VERSION 5.8 ;
BUSBITCHARS "[]" ;
DIVIDERCHAR "/" ;
UNITS
    DATABASE MICRONS 1000 ;
END UNITS

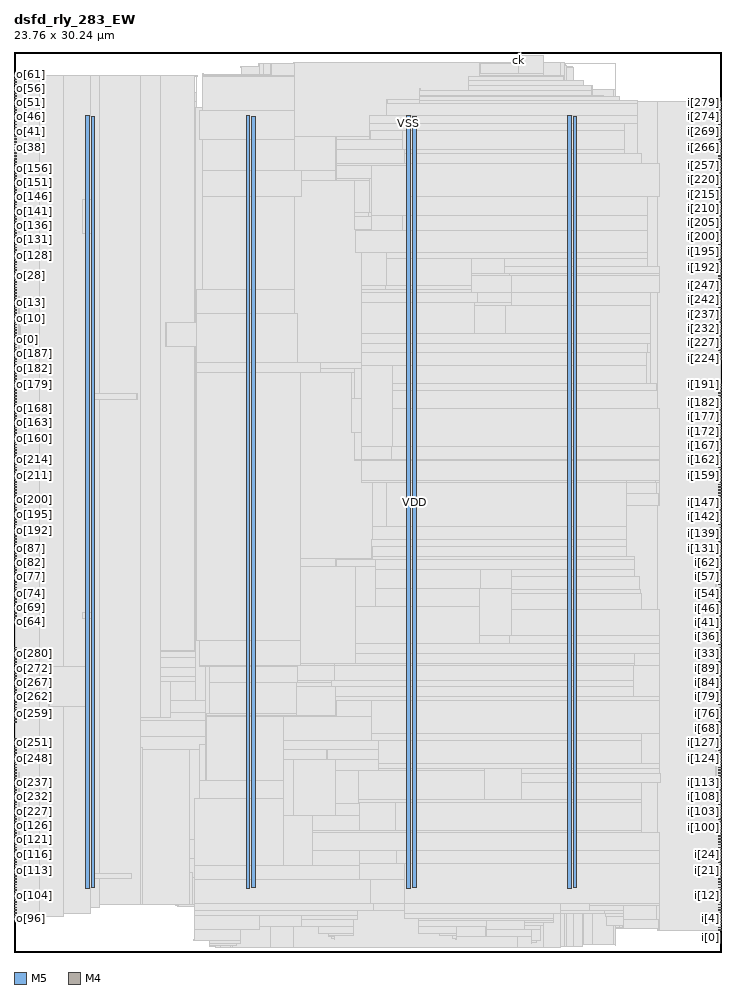
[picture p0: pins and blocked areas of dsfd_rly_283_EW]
MACRO dsfd_rly_283_EW
  FOREIGN dsfd_rly_283_EW 0 0 ;
  CLASS BLOCK ;
  SIZE 23.76 BY 30.24 ;
  PIN ck
    DIRECTION INPUT ;
    USE SIGNAL ;
    PORT
      LAYER M5 ;
        RECT  16.944 30.156 16.968 30.24 ;
    END
  END ck
  PIN i[0]
    DIRECTION INPUT ;
    USE SIGNAL ;
    PORT
      LAYER M4 ;
        RECT  23.676 0.72 23.76 0.744 ;
    END
  END i[0]
  PIN i[100]
    DIRECTION INPUT ;
    USE SIGNAL ;
    PORT
      LAYER M4 ;
        RECT  23.676 4.176 23.76 4.2 ;
    END
  END i[100]
  PIN i[101]
    DIRECTION INPUT ;
    USE SIGNAL ;
    PORT
      LAYER M4 ;
        RECT  23.676 4.272 23.76 4.296 ;
    END
  END i[101]
  PIN i[102]
    DIRECTION INPUT ;
    USE SIGNAL ;
    PORT
      LAYER M4 ;
        RECT  23.676 4.368 23.76 4.392 ;
    END
  END i[102]
  PIN i[103]
    DIRECTION INPUT ;
    USE SIGNAL ;
    PORT
      LAYER M4 ;
        RECT  23.676 4.464 23.76 4.488 ;
    END
  END i[103]
  PIN i[104]
    DIRECTION INPUT ;
    USE SIGNAL ;
    PORT
      LAYER M4 ;
        RECT  23.676 4.56 23.76 4.584 ;
    END
  END i[104]
  PIN i[105]
    DIRECTION INPUT ;
    USE SIGNAL ;
    PORT
      LAYER M4 ;
        RECT  23.676 4.656 23.76 4.68 ;
    END
  END i[105]
  PIN i[106]
    DIRECTION INPUT ;
    USE SIGNAL ;
    PORT
      LAYER M4 ;
        RECT  23.676 4.752 23.76 4.776 ;
    END
  END i[106]
  PIN i[107]
    DIRECTION INPUT ;
    USE SIGNAL ;
    PORT
      LAYER M4 ;
        RECT  23.676 4.848 23.76 4.872 ;
    END
  END i[107]
  PIN i[108]
    DIRECTION INPUT ;
    USE SIGNAL ;
    PORT
      LAYER M4 ;
        RECT  23.676 4.944 23.76 4.968 ;
    END
  END i[108]
  PIN i[109]
    DIRECTION INPUT ;
    USE SIGNAL ;
    PORT
      LAYER M4 ;
        RECT  23.676 5.04 23.76 5.064 ;
    END
  END i[109]
  PIN i[10]
    DIRECTION INPUT ;
    USE SIGNAL ;
    PORT
      LAYER M4 ;
        RECT  23.676 1.68 23.76 1.704 ;
    END
  END i[10]
  PIN i[110]
    DIRECTION INPUT ;
    USE SIGNAL ;
    PORT
      LAYER M4 ;
        RECT  23.676 5.136 23.76 5.16 ;
    END
  END i[110]
  PIN i[111]
    DIRECTION INPUT ;
    USE SIGNAL ;
    PORT
      LAYER M4 ;
        RECT  23.676 5.232 23.76 5.256 ;
    END
  END i[111]
  PIN i[112]
    DIRECTION INPUT ;
    USE SIGNAL ;
    PORT
      LAYER M4 ;
        RECT  23.676 5.328 23.76 5.352 ;
    END
  END i[112]
  PIN i[113]
    DIRECTION INPUT ;
    USE SIGNAL ;
    PORT
      LAYER M4 ;
        RECT  23.676 5.424 23.76 5.448 ;
    END
  END i[113]
  PIN i[114]
    DIRECTION INPUT ;
    USE SIGNAL ;
    PORT
      LAYER M4 ;
        RECT  23.676 5.52 23.76 5.544 ;
    END
  END i[114]
  PIN i[115]
    DIRECTION INPUT ;
    USE SIGNAL ;
    PORT
      LAYER M4 ;
        RECT  23.676 5.616 23.76 5.64 ;
    END
  END i[115]
  PIN i[116]
    DIRECTION INPUT ;
    USE SIGNAL ;
    PORT
      LAYER M4 ;
        RECT  23.676 5.712 23.76 5.736 ;
    END
  END i[116]
  PIN i[117]
    DIRECTION INPUT ;
    USE SIGNAL ;
    PORT
      LAYER M4 ;
        RECT  23.676 5.808 23.76 5.832 ;
    END
  END i[117]
  PIN i[118]
    DIRECTION INPUT ;
    USE SIGNAL ;
    PORT
      LAYER M4 ;
        RECT  23.676 5.904 23.76 5.928 ;
    END
  END i[118]
  PIN i[119]
    DIRECTION INPUT ;
    USE SIGNAL ;
    PORT
      LAYER M4 ;
        RECT  23.676 6 23.76 6.024 ;
    END
  END i[119]
  PIN i[11]
    DIRECTION INPUT ;
    USE SIGNAL ;
    PORT
      LAYER M4 ;
        RECT  23.676 1.776 23.76 1.8 ;
    END
  END i[11]
  PIN i[120]
    DIRECTION INPUT ;
    USE SIGNAL ;
    PORT
      LAYER M4 ;
        RECT  23.676 6.096 23.76 6.12 ;
    END
  END i[120]
  PIN i[121]
    DIRECTION INPUT ;
    USE SIGNAL ;
    PORT
      LAYER M4 ;
        RECT  23.676 6.192 23.76 6.216 ;
    END
  END i[121]
  PIN i[122]
    DIRECTION INPUT ;
    USE SIGNAL ;
    PORT
      LAYER M4 ;
        RECT  23.676 6.288 23.76 6.312 ;
    END
  END i[122]
  PIN i[123]
    DIRECTION INPUT ;
    USE SIGNAL ;
    PORT
      LAYER M4 ;
        RECT  23.676 6.384 23.76 6.408 ;
    END
  END i[123]
  PIN i[124]
    DIRECTION INPUT ;
    USE SIGNAL ;
    PORT
      LAYER M4 ;
        RECT  23.676 6.48 23.76 6.504 ;
    END
  END i[124]
  PIN i[125]
    DIRECTION INPUT ;
    USE SIGNAL ;
    PORT
      LAYER M4 ;
        RECT  23.676 6.576 23.76 6.6 ;
    END
  END i[125]
  PIN i[126]
    DIRECTION INPUT ;
    USE SIGNAL ;
    PORT
      LAYER M4 ;
        RECT  23.676 6.672 23.76 6.696 ;
    END
  END i[126]
  PIN i[127]
    DIRECTION INPUT ;
    USE SIGNAL ;
    PORT
      LAYER M4 ;
        RECT  23.676 6.768 23.76 6.792 ;
    END
  END i[127]
  PIN i[128]
    DIRECTION INPUT ;
    USE SIGNAL ;
    PORT
      LAYER M4 ;
        RECT  23.676 13.008 23.76 13.032 ;
    END
  END i[128]
  PIN i[129]
    DIRECTION INPUT ;
    USE SIGNAL ;
    PORT
      LAYER M4 ;
        RECT  23.676 13.104 23.76 13.128 ;
    END
  END i[129]
  PIN i[12]
    DIRECTION INPUT ;
    USE SIGNAL ;
    PORT
      LAYER M4 ;
        RECT  23.676 1.872 23.76 1.896 ;
    END
  END i[12]
  PIN i[130]
    DIRECTION INPUT ;
    USE SIGNAL ;
    PORT
      LAYER M4 ;
        RECT  23.676 13.2 23.76 13.224 ;
    END
  END i[130]
  PIN i[131]
    DIRECTION INPUT ;
    USE SIGNAL ;
    PORT
      LAYER M4 ;
        RECT  23.676 13.296 23.76 13.32 ;
    END
  END i[131]
  PIN i[132]
    DIRECTION INPUT ;
    USE SIGNAL ;
    PORT
      LAYER M4 ;
        RECT  23.676 13.392 23.76 13.416 ;
    END
  END i[132]
  PIN i[133]
    DIRECTION INPUT ;
    USE SIGNAL ;
    PORT
      LAYER M4 ;
        RECT  23.676 13.488 23.76 13.512 ;
    END
  END i[133]
  PIN i[134]
    DIRECTION INPUT ;
    USE SIGNAL ;
    PORT
      LAYER M4 ;
        RECT  23.676 13.584 23.76 13.608 ;
    END
  END i[134]
  PIN i[135]
    DIRECTION INPUT ;
    USE SIGNAL ;
    PORT
      LAYER M4 ;
        RECT  23.676 13.68 23.76 13.704 ;
    END
  END i[135]
  PIN i[136]
    DIRECTION INPUT ;
    USE SIGNAL ;
    PORT
      LAYER M4 ;
        RECT  23.676 13.776 23.76 13.8 ;
    END
  END i[136]
  PIN i[137]
    DIRECTION INPUT ;
    USE SIGNAL ;
    PORT
      LAYER M4 ;
        RECT  23.676 13.872 23.76 13.896 ;
    END
  END i[137]
  PIN i[138]
    DIRECTION INPUT ;
    USE SIGNAL ;
    PORT
      LAYER M4 ;
        RECT  23.676 13.968 23.76 13.992 ;
    END
  END i[138]
  PIN i[139]
    DIRECTION INPUT ;
    USE SIGNAL ;
    PORT
      LAYER M4 ;
        RECT  23.676 14.064 23.76 14.088 ;
    END
  END i[139]
  PIN i[13]
    DIRECTION INPUT ;
    USE SIGNAL ;
    PORT
      LAYER M4 ;
        RECT  23.676 1.968 23.76 1.992 ;
    END
  END i[13]
  PIN i[140]
    DIRECTION INPUT ;
    USE SIGNAL ;
    PORT
      LAYER M4 ;
        RECT  23.676 14.16 23.76 14.184 ;
    END
  END i[140]
  PIN i[141]
    DIRECTION INPUT ;
    USE SIGNAL ;
    PORT
      LAYER M4 ;
        RECT  23.676 14.256 23.76 14.28 ;
    END
  END i[141]
  PIN i[142]
    DIRECTION INPUT ;
    USE SIGNAL ;
    PORT
      LAYER M4 ;
        RECT  23.676 14.352 23.76 14.376 ;
    END
  END i[142]
  PIN i[143]
    DIRECTION INPUT ;
    USE SIGNAL ;
    PORT
      LAYER M4 ;
        RECT  23.676 14.448 23.76 14.472 ;
    END
  END i[143]
  PIN i[144]
    DIRECTION INPUT ;
    USE SIGNAL ;
    PORT
      LAYER M4 ;
        RECT  23.676 14.544 23.76 14.568 ;
    END
  END i[144]
  PIN i[145]
    DIRECTION INPUT ;
    USE SIGNAL ;
    PORT
      LAYER M4 ;
        RECT  23.676 14.64 23.76 14.664 ;
    END
  END i[145]
  PIN i[146]
    DIRECTION INPUT ;
    USE SIGNAL ;
    PORT
      LAYER M4 ;
        RECT  23.676 14.736 23.76 14.76 ;
    END
  END i[146]
  PIN i[147]
    DIRECTION INPUT ;
    USE SIGNAL ;
    PORT
      LAYER M4 ;
        RECT  23.676 14.832 23.76 14.856 ;
    END
  END i[147]
  PIN i[148]
    DIRECTION INPUT ;
    USE SIGNAL ;
    PORT
      LAYER M4 ;
        RECT  23.676 14.928 23.76 14.952 ;
    END
  END i[148]
  PIN i[149]
    DIRECTION INPUT ;
    USE SIGNAL ;
    PORT
      LAYER M4 ;
        RECT  23.676 15.024 23.76 15.048 ;
    END
  END i[149]
  PIN i[14]
    DIRECTION INPUT ;
    USE SIGNAL ;
    PORT
      LAYER M4 ;
        RECT  23.676 2.064 23.76 2.088 ;
    END
  END i[14]
  PIN i[150]
    DIRECTION INPUT ;
    USE SIGNAL ;
    PORT
      LAYER M4 ;
        RECT  23.676 15.12 23.76 15.144 ;
    END
  END i[150]
  PIN i[151]
    DIRECTION INPUT ;
    USE SIGNAL ;
    PORT
      LAYER M4 ;
        RECT  23.676 15.216 23.76 15.24 ;
    END
  END i[151]
  PIN i[152]
    DIRECTION INPUT ;
    USE SIGNAL ;
    PORT
      LAYER M4 ;
        RECT  23.676 15.312 23.76 15.336 ;
    END
  END i[152]
  PIN i[153]
    DIRECTION INPUT ;
    USE SIGNAL ;
    PORT
      LAYER M4 ;
        RECT  23.676 15.408 23.76 15.432 ;
    END
  END i[153]
  PIN i[154]
    DIRECTION INPUT ;
    USE SIGNAL ;
    PORT
      LAYER M4 ;
        RECT  23.676 15.504 23.76 15.528 ;
    END
  END i[154]
  PIN i[155]
    DIRECTION INPUT ;
    USE SIGNAL ;
    PORT
      LAYER M4 ;
        RECT  23.676 15.6 23.76 15.624 ;
    END
  END i[155]
  PIN i[156]
    DIRECTION INPUT ;
    USE SIGNAL ;
    PORT
      LAYER M4 ;
        RECT  23.676 15.696 23.76 15.72 ;
    END
  END i[156]
  PIN i[157]
    DIRECTION INPUT ;
    USE SIGNAL ;
    PORT
      LAYER M4 ;
        RECT  23.676 15.792 23.76 15.816 ;
    END
  END i[157]
  PIN i[158]
    DIRECTION INPUT ;
    USE SIGNAL ;
    PORT
      LAYER M4 ;
        RECT  23.676 15.888 23.76 15.912 ;
    END
  END i[158]
  PIN i[159]
    DIRECTION INPUT ;
    USE SIGNAL ;
    PORT
      LAYER M4 ;
        RECT  23.676 15.984 23.76 16.008 ;
    END
  END i[159]
  PIN i[15]
    DIRECTION INPUT ;
    USE SIGNAL ;
    PORT
      LAYER M4 ;
        RECT  23.676 2.16 23.76 2.184 ;
    END
  END i[15]
  PIN i[160]
    DIRECTION INPUT ;
    USE SIGNAL ;
    PORT
      LAYER M4 ;
        RECT  23.676 16.08 23.76 16.104 ;
    END
  END i[160]
  PIN i[161]
    DIRECTION INPUT ;
    USE SIGNAL ;
    PORT
      LAYER M4 ;
        RECT  23.676 16.176 23.76 16.2 ;
    END
  END i[161]
  PIN i[162]
    DIRECTION INPUT ;
    USE SIGNAL ;
    PORT
      LAYER M4 ;
        RECT  23.676 16.272 23.76 16.296 ;
    END
  END i[162]
  PIN i[163]
    DIRECTION INPUT ;
    USE SIGNAL ;
    PORT
      LAYER M4 ;
        RECT  23.676 16.368 23.76 16.392 ;
    END
  END i[163]
  PIN i[164]
    DIRECTION INPUT ;
    USE SIGNAL ;
    PORT
      LAYER M4 ;
        RECT  23.676 16.464 23.76 16.488 ;
    END
  END i[164]
  PIN i[165]
    DIRECTION INPUT ;
    USE SIGNAL ;
    PORT
      LAYER M4 ;
        RECT  23.676 16.56 23.76 16.584 ;
    END
  END i[165]
  PIN i[166]
    DIRECTION INPUT ;
    USE SIGNAL ;
    PORT
      LAYER M4 ;
        RECT  23.676 16.656 23.76 16.68 ;
    END
  END i[166]
  PIN i[167]
    DIRECTION INPUT ;
    USE SIGNAL ;
    PORT
      LAYER M4 ;
        RECT  23.676 16.752 23.76 16.776 ;
    END
  END i[167]
  PIN i[168]
    DIRECTION INPUT ;
    USE SIGNAL ;
    PORT
      LAYER M4 ;
        RECT  23.676 16.848 23.76 16.872 ;
    END
  END i[168]
  PIN i[169]
    DIRECTION INPUT ;
    USE SIGNAL ;
    PORT
      LAYER M4 ;
        RECT  23.676 16.944 23.76 16.968 ;
    END
  END i[169]
  PIN i[16]
    DIRECTION INPUT ;
    USE SIGNAL ;
    PORT
      LAYER M4 ;
        RECT  23.676 2.256 23.76 2.28 ;
    END
  END i[16]
  PIN i[170]
    DIRECTION INPUT ;
    USE SIGNAL ;
    PORT
      LAYER M4 ;
        RECT  23.676 17.04 23.76 17.064 ;
    END
  END i[170]
  PIN i[171]
    DIRECTION INPUT ;
    USE SIGNAL ;
    PORT
      LAYER M4 ;
        RECT  23.676 17.136 23.76 17.16 ;
    END
  END i[171]
  PIN i[172]
    DIRECTION INPUT ;
    USE SIGNAL ;
    PORT
      LAYER M4 ;
        RECT  23.676 17.232 23.76 17.256 ;
    END
  END i[172]
  PIN i[173]
    DIRECTION INPUT ;
    USE SIGNAL ;
    PORT
      LAYER M4 ;
        RECT  23.676 17.328 23.76 17.352 ;
    END
  END i[173]
  PIN i[174]
    DIRECTION INPUT ;
    USE SIGNAL ;
    PORT
      LAYER M4 ;
        RECT  23.676 17.424 23.76 17.448 ;
    END
  END i[174]
  PIN i[175]
    DIRECTION INPUT ;
    USE SIGNAL ;
    PORT
      LAYER M4 ;
        RECT  23.676 17.52 23.76 17.544 ;
    END
  END i[175]
  PIN i[176]
    DIRECTION INPUT ;
    USE SIGNAL ;
    PORT
      LAYER M4 ;
        RECT  23.676 17.616 23.76 17.64 ;
    END
  END i[176]
  PIN i[177]
    DIRECTION INPUT ;
    USE SIGNAL ;
    PORT
      LAYER M4 ;
        RECT  23.676 17.712 23.76 17.736 ;
    END
  END i[177]
  PIN i[178]
    DIRECTION INPUT ;
    USE SIGNAL ;
    PORT
      LAYER M4 ;
        RECT  23.676 17.808 23.76 17.832 ;
    END
  END i[178]
  PIN i[179]
    DIRECTION INPUT ;
    USE SIGNAL ;
    PORT
      LAYER M4 ;
        RECT  23.676 17.904 23.76 17.928 ;
    END
  END i[179]
  PIN i[17]
    DIRECTION INPUT ;
    USE SIGNAL ;
    PORT
      LAYER M4 ;
        RECT  23.676 2.352 23.76 2.376 ;
    END
  END i[17]
  PIN i[180]
    DIRECTION INPUT ;
    USE SIGNAL ;
    PORT
      LAYER M4 ;
        RECT  23.676 18 23.76 18.024 ;
    END
  END i[180]
  PIN i[181]
    DIRECTION INPUT ;
    USE SIGNAL ;
    PORT
      LAYER M4 ;
        RECT  23.676 18.096 23.76 18.12 ;
    END
  END i[181]
  PIN i[182]
    DIRECTION INPUT ;
    USE SIGNAL ;
    PORT
      LAYER M4 ;
        RECT  23.676 18.192 23.76 18.216 ;
    END
  END i[182]
  PIN i[183]
    DIRECTION INPUT ;
    USE SIGNAL ;
    PORT
      LAYER M4 ;
        RECT  23.676 18.288 23.76 18.312 ;
    END
  END i[183]
  PIN i[184]
    DIRECTION INPUT ;
    USE SIGNAL ;
    PORT
      LAYER M4 ;
        RECT  23.676 18.384 23.76 18.408 ;
    END
  END i[184]
  PIN i[185]
    DIRECTION INPUT ;
    USE SIGNAL ;
    PORT
      LAYER M4 ;
        RECT  23.676 18.48 23.76 18.504 ;
    END
  END i[185]
  PIN i[186]
    DIRECTION INPUT ;
    USE SIGNAL ;
    PORT
      LAYER M4 ;
        RECT  23.676 18.576 23.76 18.6 ;
    END
  END i[186]
  PIN i[187]
    DIRECTION INPUT ;
    USE SIGNAL ;
    PORT
      LAYER M4 ;
        RECT  23.676 18.672 23.76 18.696 ;
    END
  END i[187]
  PIN i[188]
    DIRECTION INPUT ;
    USE SIGNAL ;
    PORT
      LAYER M4 ;
        RECT  23.676 18.768 23.76 18.792 ;
    END
  END i[188]
  PIN i[189]
    DIRECTION INPUT ;
    USE SIGNAL ;
    PORT
      LAYER M4 ;
        RECT  23.676 18.864 23.76 18.888 ;
    END
  END i[189]
  PIN i[18]
    DIRECTION INPUT ;
    USE SIGNAL ;
    PORT
      LAYER M4 ;
        RECT  23.676 2.448 23.76 2.472 ;
    END
  END i[18]
  PIN i[190]
    DIRECTION INPUT ;
    USE SIGNAL ;
    PORT
      LAYER M4 ;
        RECT  23.676 18.96 23.76 18.984 ;
    END
  END i[190]
  PIN i[191]
    DIRECTION INPUT ;
    USE SIGNAL ;
    PORT
      LAYER M4 ;
        RECT  23.676 19.056 23.76 19.08 ;
    END
  END i[191]
  PIN i[192]
    DIRECTION INPUT ;
    USE SIGNAL ;
    PORT
      LAYER M4 ;
        RECT  23.676 22.992 23.76 23.016 ;
    END
  END i[192]
  PIN i[193]
    DIRECTION INPUT ;
    USE SIGNAL ;
    PORT
      LAYER M4 ;
        RECT  23.676 23.088 23.76 23.112 ;
    END
  END i[193]
  PIN i[194]
    DIRECTION INPUT ;
    USE SIGNAL ;
    PORT
      LAYER M4 ;
        RECT  23.676 23.184 23.76 23.208 ;
    END
  END i[194]
  PIN i[195]
    DIRECTION INPUT ;
    USE SIGNAL ;
    PORT
      LAYER M4 ;
        RECT  23.676 23.28 23.76 23.304 ;
    END
  END i[195]
  PIN i[196]
    DIRECTION INPUT ;
    USE SIGNAL ;
    PORT
      LAYER M4 ;
        RECT  23.676 23.376 23.76 23.4 ;
    END
  END i[196]
  PIN i[197]
    DIRECTION INPUT ;
    USE SIGNAL ;
    PORT
      LAYER M4 ;
        RECT  23.676 23.472 23.76 23.496 ;
    END
  END i[197]
  PIN i[198]
    DIRECTION INPUT ;
    USE SIGNAL ;
    PORT
      LAYER M4 ;
        RECT  23.676 23.568 23.76 23.592 ;
    END
  END i[198]
  PIN i[199]
    DIRECTION INPUT ;
    USE SIGNAL ;
    PORT
      LAYER M4 ;
        RECT  23.676 23.664 23.76 23.688 ;
    END
  END i[199]
  PIN i[19]
    DIRECTION INPUT ;
    USE SIGNAL ;
    PORT
      LAYER M4 ;
        RECT  23.676 2.544 23.76 2.568 ;
    END
  END i[19]
  PIN i[1]
    DIRECTION INPUT ;
    USE SIGNAL ;
    PORT
      LAYER M4 ;
        RECT  23.676 0.816 23.76 0.84 ;
    END
  END i[1]
  PIN i[200]
    DIRECTION INPUT ;
    USE SIGNAL ;
    PORT
      LAYER M4 ;
        RECT  23.676 23.76 23.76 23.784 ;
    END
  END i[200]
  PIN i[201]
    DIRECTION INPUT ;
    USE SIGNAL ;
    PORT
      LAYER M4 ;
        RECT  23.676 23.856 23.76 23.88 ;
    END
  END i[201]
  PIN i[202]
    DIRECTION INPUT ;
    USE SIGNAL ;
    PORT
      LAYER M4 ;
        RECT  23.676 23.952 23.76 23.976 ;
    END
  END i[202]
  PIN i[203]
    DIRECTION INPUT ;
    USE SIGNAL ;
    PORT
      LAYER M4 ;
        RECT  23.676 24.048 23.76 24.072 ;
    END
  END i[203]
  PIN i[204]
    DIRECTION INPUT ;
    USE SIGNAL ;
    PORT
      LAYER M4 ;
        RECT  23.676 24.144 23.76 24.168 ;
    END
  END i[204]
  PIN i[205]
    DIRECTION INPUT ;
    USE SIGNAL ;
    PORT
      LAYER M4 ;
        RECT  23.676 24.24 23.76 24.264 ;
    END
  END i[205]
  PIN i[206]
    DIRECTION INPUT ;
    USE SIGNAL ;
    PORT
      LAYER M4 ;
        RECT  23.676 24.336 23.76 24.36 ;
    END
  END i[206]
  PIN i[207]
    DIRECTION INPUT ;
    USE SIGNAL ;
    PORT
      LAYER M4 ;
        RECT  23.676 24.432 23.76 24.456 ;
    END
  END i[207]
  PIN i[208]
    DIRECTION INPUT ;
    USE SIGNAL ;
    PORT
      LAYER M4 ;
        RECT  23.676 24.528 23.76 24.552 ;
    END
  END i[208]
  PIN i[209]
    DIRECTION INPUT ;
    USE SIGNAL ;
    PORT
      LAYER M4 ;
        RECT  23.676 24.624 23.76 24.648 ;
    END
  END i[209]
  PIN i[20]
    DIRECTION INPUT ;
    USE SIGNAL ;
    PORT
      LAYER M4 ;
        RECT  23.676 2.64 23.76 2.664 ;
    END
  END i[20]
  PIN i[210]
    DIRECTION INPUT ;
    USE SIGNAL ;
    PORT
      LAYER M4 ;
        RECT  23.676 24.72 23.76 24.744 ;
    END
  END i[210]
  PIN i[211]
    DIRECTION INPUT ;
    USE SIGNAL ;
    PORT
      LAYER M4 ;
        RECT  23.676 24.816 23.76 24.84 ;
    END
  END i[211]
  PIN i[212]
    DIRECTION INPUT ;
    USE SIGNAL ;
    PORT
      LAYER M4 ;
        RECT  23.676 24.912 23.76 24.936 ;
    END
  END i[212]
  PIN i[213]
    DIRECTION INPUT ;
    USE SIGNAL ;
    PORT
      LAYER M4 ;
        RECT  23.676 25.008 23.76 25.032 ;
    END
  END i[213]
  PIN i[214]
    DIRECTION INPUT ;
    USE SIGNAL ;
    PORT
      LAYER M4 ;
        RECT  23.676 25.104 23.76 25.128 ;
    END
  END i[214]
  PIN i[215]
    DIRECTION INPUT ;
    USE SIGNAL ;
    PORT
      LAYER M4 ;
        RECT  23.676 25.2 23.76 25.224 ;
    END
  END i[215]
  PIN i[216]
    DIRECTION INPUT ;
    USE SIGNAL ;
    PORT
      LAYER M4 ;
        RECT  23.676 25.296 23.76 25.32 ;
    END
  END i[216]
  PIN i[217]
    DIRECTION INPUT ;
    USE SIGNAL ;
    PORT
      LAYER M4 ;
        RECT  23.676 25.392 23.76 25.416 ;
    END
  END i[217]
  PIN i[218]
    DIRECTION INPUT ;
    USE SIGNAL ;
    PORT
      LAYER M4 ;
        RECT  23.676 25.488 23.76 25.512 ;
    END
  END i[218]
  PIN i[219]
    DIRECTION INPUT ;
    USE SIGNAL ;
    PORT
      LAYER M4 ;
        RECT  23.676 25.584 23.76 25.608 ;
    END
  END i[219]
  PIN i[21]
    DIRECTION INPUT ;
    USE SIGNAL ;
    PORT
      LAYER M4 ;
        RECT  23.676 2.736 23.76 2.76 ;
    END
  END i[21]
  PIN i[220]
    DIRECTION INPUT ;
    USE SIGNAL ;
    PORT
      LAYER M4 ;
        RECT  23.676 25.68 23.76 25.704 ;
    END
  END i[220]
  PIN i[221]
    DIRECTION INPUT ;
    USE SIGNAL ;
    PORT
      LAYER M4 ;
        RECT  23.676 25.776 23.76 25.8 ;
    END
  END i[221]
  PIN i[222]
    DIRECTION INPUT ;
    USE SIGNAL ;
    PORT
      LAYER M4 ;
        RECT  23.676 25.872 23.76 25.896 ;
    END
  END i[222]
  PIN i[223]
    DIRECTION INPUT ;
    USE SIGNAL ;
    PORT
      LAYER M4 ;
        RECT  23.676 25.968 23.76 25.992 ;
    END
  END i[223]
  PIN i[224]
    DIRECTION INPUT ;
    USE SIGNAL ;
    PORT
      LAYER M4 ;
        RECT  23.676 19.92 23.76 19.944 ;
    END
  END i[224]
  PIN i[225]
    DIRECTION INPUT ;
    USE SIGNAL ;
    PORT
      LAYER M4 ;
        RECT  23.676 20.016 23.76 20.04 ;
    END
  END i[225]
  PIN i[226]
    DIRECTION INPUT ;
    USE SIGNAL ;
    PORT
      LAYER M4 ;
        RECT  23.676 20.112 23.76 20.136 ;
    END
  END i[226]
  PIN i[227]
    DIRECTION INPUT ;
    USE SIGNAL ;
    PORT
      LAYER M4 ;
        RECT  23.676 20.208 23.76 20.232 ;
    END
  END i[227]
  PIN i[228]
    DIRECTION INPUT ;
    USE SIGNAL ;
    PORT
      LAYER M4 ;
        RECT  23.676 20.304 23.76 20.328 ;
    END
  END i[228]
  PIN i[229]
    DIRECTION INPUT ;
    USE SIGNAL ;
    PORT
      LAYER M4 ;
        RECT  23.676 20.4 23.76 20.424 ;
    END
  END i[229]
  PIN i[22]
    DIRECTION INPUT ;
    USE SIGNAL ;
    PORT
      LAYER M4 ;
        RECT  23.676 2.832 23.76 2.856 ;
    END
  END i[22]
  PIN i[230]
    DIRECTION INPUT ;
    USE SIGNAL ;
    PORT
      LAYER M4 ;
        RECT  23.676 20.496 23.76 20.52 ;
    END
  END i[230]
  PIN i[231]
    DIRECTION INPUT ;
    USE SIGNAL ;
    PORT
      LAYER M4 ;
        RECT  23.676 20.592 23.76 20.616 ;
    END
  END i[231]
  PIN i[232]
    DIRECTION INPUT ;
    USE SIGNAL ;
    PORT
      LAYER M4 ;
        RECT  23.676 20.688 23.76 20.712 ;
    END
  END i[232]
  PIN i[233]
    DIRECTION INPUT ;
    USE SIGNAL ;
    PORT
      LAYER M4 ;
        RECT  23.676 20.784 23.76 20.808 ;
    END
  END i[233]
  PIN i[234]
    DIRECTION INPUT ;
    USE SIGNAL ;
    PORT
      LAYER M4 ;
        RECT  23.676 20.88 23.76 20.904 ;
    END
  END i[234]
  PIN i[235]
    DIRECTION INPUT ;
    USE SIGNAL ;
    PORT
      LAYER M4 ;
        RECT  23.676 20.976 23.76 21 ;
    END
  END i[235]
  PIN i[236]
    DIRECTION INPUT ;
    USE SIGNAL ;
    PORT
      LAYER M4 ;
        RECT  23.676 21.072 23.76 21.096 ;
    END
  END i[236]
  PIN i[237]
    DIRECTION INPUT ;
    USE SIGNAL ;
    PORT
      LAYER M4 ;
        RECT  23.676 21.168 23.76 21.192 ;
    END
  END i[237]
  PIN i[238]
    DIRECTION INPUT ;
    USE SIGNAL ;
    PORT
      LAYER M4 ;
        RECT  23.676 21.264 23.76 21.288 ;
    END
  END i[238]
  PIN i[239]
    DIRECTION INPUT ;
    USE SIGNAL ;
    PORT
      LAYER M4 ;
        RECT  23.676 21.36 23.76 21.384 ;
    END
  END i[239]
  PIN i[23]
    DIRECTION INPUT ;
    USE SIGNAL ;
    PORT
      LAYER M4 ;
        RECT  23.676 2.928 23.76 2.952 ;
    END
  END i[23]
  PIN i[240]
    DIRECTION INPUT ;
    USE SIGNAL ;
    PORT
      LAYER M4 ;
        RECT  23.676 21.456 23.76 21.48 ;
    END
  END i[240]
  PIN i[241]
    DIRECTION INPUT ;
    USE SIGNAL ;
    PORT
      LAYER M4 ;
        RECT  23.676 21.552 23.76 21.576 ;
    END
  END i[241]
  PIN i[242]
    DIRECTION INPUT ;
    USE SIGNAL ;
    PORT
      LAYER M4 ;
        RECT  23.676 21.648 23.76 21.672 ;
    END
  END i[242]
  PIN i[243]
    DIRECTION INPUT ;
    USE SIGNAL ;
    PORT
      LAYER M4 ;
        RECT  23.676 21.744 23.76 21.768 ;
    END
  END i[243]
  PIN i[244]
    DIRECTION INPUT ;
    USE SIGNAL ;
    PORT
      LAYER M4 ;
        RECT  23.676 21.84 23.76 21.864 ;
    END
  END i[244]
  PIN i[245]
    DIRECTION INPUT ;
    USE SIGNAL ;
    PORT
      LAYER M4 ;
        RECT  23.676 21.936 23.76 21.96 ;
    END
  END i[245]
  PIN i[246]
    DIRECTION INPUT ;
    USE SIGNAL ;
    PORT
      LAYER M4 ;
        RECT  23.676 22.032 23.76 22.056 ;
    END
  END i[246]
  PIN i[247]
    DIRECTION INPUT ;
    USE SIGNAL ;
    PORT
      LAYER M4 ;
        RECT  23.676 22.128 23.76 22.152 ;
    END
  END i[247]
  PIN i[248]
    DIRECTION INPUT ;
    USE SIGNAL ;
    PORT
      LAYER M4 ;
        RECT  23.676 22.224 23.76 22.248 ;
    END
  END i[248]
  PIN i[249]
    DIRECTION INPUT ;
    USE SIGNAL ;
    PORT
      LAYER M4 ;
        RECT  23.676 22.32 23.76 22.344 ;
    END
  END i[249]
  PIN i[24]
    DIRECTION INPUT ;
    USE SIGNAL ;
    PORT
      LAYER M4 ;
        RECT  23.676 3.024 23.76 3.048 ;
    END
  END i[24]
  PIN i[250]
    DIRECTION INPUT ;
    USE SIGNAL ;
    PORT
      LAYER M4 ;
        RECT  23.676 22.416 23.76 22.44 ;
    END
  END i[250]
  PIN i[251]
    DIRECTION INPUT ;
    USE SIGNAL ;
    PORT
      LAYER M4 ;
        RECT  23.676 22.512 23.76 22.536 ;
    END
  END i[251]
  PIN i[252]
    DIRECTION INPUT ;
    USE SIGNAL ;
    PORT
      LAYER M4 ;
        RECT  23.676 22.608 23.76 22.632 ;
    END
  END i[252]
  PIN i[253]
    DIRECTION INPUT ;
    USE SIGNAL ;
    PORT
      LAYER M4 ;
        RECT  23.676 22.704 23.76 22.728 ;
    END
  END i[253]
  PIN i[254]
    DIRECTION INPUT ;
    USE SIGNAL ;
    PORT
      LAYER M4 ;
        RECT  23.676 22.8 23.76 22.824 ;
    END
  END i[254]
  PIN i[255]
    DIRECTION INPUT ;
    USE SIGNAL ;
    PORT
      LAYER M4 ;
        RECT  23.676 22.896 23.76 22.92 ;
    END
  END i[255]
  PIN i[256]
    DIRECTION INPUT ;
    USE SIGNAL ;
    PORT
      LAYER M4 ;
        RECT  23.676 26.064 23.76 26.088 ;
    END
  END i[256]
  PIN i[257]
    DIRECTION INPUT ;
    USE SIGNAL ;
    PORT
      LAYER M4 ;
        RECT  23.676 26.16 23.76 26.184 ;
    END
  END i[257]
  PIN i[258]
    DIRECTION INPUT ;
    USE SIGNAL ;
    PORT
      LAYER M4 ;
        RECT  23.676 26.256 23.76 26.28 ;
    END
  END i[258]
  PIN i[259]
    DIRECTION INPUT ;
    USE SIGNAL ;
    PORT
      LAYER M4 ;
        RECT  23.676 26.352 23.76 26.376 ;
    END
  END i[259]
  PIN i[25]
    DIRECTION INPUT ;
    USE SIGNAL ;
    PORT
      LAYER M4 ;
        RECT  23.676 3.12 23.76 3.144 ;
    END
  END i[25]
  PIN i[260]
    DIRECTION INPUT ;
    USE SIGNAL ;
    PORT
      LAYER M4 ;
        RECT  23.676 26.448 23.76 26.472 ;
    END
  END i[260]
  PIN i[261]
    DIRECTION INPUT ;
    USE SIGNAL ;
    PORT
      LAYER M4 ;
        RECT  23.676 26.544 23.76 26.568 ;
    END
  END i[261]
  PIN i[262]
    DIRECTION INPUT ;
    USE SIGNAL ;
    PORT
      LAYER M4 ;
        RECT  23.676 26.64 23.76 26.664 ;
    END
  END i[262]
  PIN i[263]
    DIRECTION INPUT ;
    USE SIGNAL ;
    PORT
      LAYER M4 ;
        RECT  23.676 26.736 23.76 26.76 ;
    END
  END i[263]
  PIN i[264]
    DIRECTION INPUT ;
    USE SIGNAL ;
    PORT
      LAYER M4 ;
        RECT  23.676 26.832 23.76 26.856 ;
    END
  END i[264]
  PIN i[265]
    DIRECTION INPUT ;
    USE SIGNAL ;
    PORT
      LAYER M4 ;
        RECT  23.676 26.928 23.76 26.952 ;
    END
  END i[265]
  PIN i[266]
    DIRECTION INPUT ;
    USE SIGNAL ;
    PORT
      LAYER M4 ;
        RECT  23.676 27.024 23.76 27.048 ;
    END
  END i[266]
  PIN i[267]
    DIRECTION INPUT ;
    USE SIGNAL ;
    PORT
      LAYER M4 ;
        RECT  23.676 27.12 23.76 27.144 ;
    END
  END i[267]
  PIN i[268]
    DIRECTION INPUT ;
    USE SIGNAL ;
    PORT
      LAYER M4 ;
        RECT  23.676 27.216 23.76 27.24 ;
    END
  END i[268]
  PIN i[269]
    DIRECTION INPUT ;
    USE SIGNAL ;
    PORT
      LAYER M4 ;
        RECT  23.676 27.312 23.76 27.336 ;
    END
  END i[269]
  PIN i[26]
    DIRECTION INPUT ;
    USE SIGNAL ;
    PORT
      LAYER M4 ;
        RECT  23.676 3.216 23.76 3.24 ;
    END
  END i[26]
  PIN i[270]
    DIRECTION INPUT ;
    USE SIGNAL ;
    PORT
      LAYER M4 ;
        RECT  23.676 27.408 23.76 27.432 ;
    END
  END i[270]
  PIN i[271]
    DIRECTION INPUT ;
    USE SIGNAL ;
    PORT
      LAYER M4 ;
        RECT  23.676 27.504 23.76 27.528 ;
    END
  END i[271]
  PIN i[272]
    DIRECTION INPUT ;
    USE SIGNAL ;
    PORT
      LAYER M4 ;
        RECT  23.676 27.6 23.76 27.624 ;
    END
  END i[272]
  PIN i[273]
    DIRECTION INPUT ;
    USE SIGNAL ;
    PORT
      LAYER M4 ;
        RECT  23.676 27.696 23.76 27.72 ;
    END
  END i[273]
  PIN i[274]
    DIRECTION INPUT ;
    USE SIGNAL ;
    PORT
      LAYER M4 ;
        RECT  23.676 27.792 23.76 27.816 ;
    END
  END i[274]
  PIN i[275]
    DIRECTION INPUT ;
    USE SIGNAL ;
    PORT
      LAYER M4 ;
        RECT  23.676 27.888 23.76 27.912 ;
    END
  END i[275]
  PIN i[276]
    DIRECTION INPUT ;
    USE SIGNAL ;
    PORT
      LAYER M4 ;
        RECT  23.676 27.984 23.76 28.008 ;
    END
  END i[276]
  PIN i[277]
    DIRECTION INPUT ;
    USE SIGNAL ;
    PORT
      LAYER M4 ;
        RECT  23.676 28.08 23.76 28.104 ;
    END
  END i[277]
  PIN i[278]
    DIRECTION INPUT ;
    USE SIGNAL ;
    PORT
      LAYER M4 ;
        RECT  23.676 28.176 23.76 28.2 ;
    END
  END i[278]
  PIN i[279]
    DIRECTION INPUT ;
    USE SIGNAL ;
    PORT
      LAYER M4 ;
        RECT  23.676 28.272 23.76 28.296 ;
    END
  END i[279]
  PIN i[27]
    DIRECTION INPUT ;
    USE SIGNAL ;
    PORT
      LAYER M4 ;
        RECT  23.676 3.312 23.76 3.336 ;
    END
  END i[27]
  PIN i[280]
    DIRECTION INPUT ;
    USE SIGNAL ;
    PORT
      LAYER M4 ;
        RECT  23.676 28.368 23.76 28.392 ;
    END
  END i[280]
  PIN i[281]
    DIRECTION INPUT ;
    USE SIGNAL ;
    PORT
      LAYER M4 ;
        RECT  23.676 28.464 23.76 28.488 ;
    END
  END i[281]
  PIN i[282]
    DIRECTION INPUT ;
    USE SIGNAL ;
    PORT
      LAYER M4 ;
        RECT  23.676 28.56 23.76 28.584 ;
    END
  END i[282]
  PIN i[28]
    DIRECTION INPUT ;
    USE SIGNAL ;
    PORT
      LAYER M4 ;
        RECT  23.676 3.408 23.76 3.432 ;
    END
  END i[28]
  PIN i[29]
    DIRECTION INPUT ;
    USE SIGNAL ;
    PORT
      LAYER M4 ;
        RECT  23.676 3.504 23.76 3.528 ;
    END
  END i[29]
  PIN i[2]
    DIRECTION INPUT ;
    USE SIGNAL ;
    PORT
      LAYER M4 ;
        RECT  23.676 0.912 23.76 0.936 ;
    END
  END i[2]
  PIN i[30]
    DIRECTION INPUT ;
    USE SIGNAL ;
    PORT
      LAYER M4 ;
        RECT  23.676 3.6 23.76 3.624 ;
    END
  END i[30]
  PIN i[31]
    DIRECTION INPUT ;
    USE SIGNAL ;
    PORT
      LAYER M4 ;
        RECT  23.676 3.696 23.76 3.72 ;
    END
  END i[31]
  PIN i[32]
    DIRECTION INPUT ;
    USE SIGNAL ;
    PORT
      LAYER M4 ;
        RECT  23.676 9.936 23.76 9.96 ;
    END
  END i[32]
  PIN i[33]
    DIRECTION INPUT ;
    USE SIGNAL ;
    PORT
      LAYER M4 ;
        RECT  23.676 10.032 23.76 10.056 ;
    END
  END i[33]
  PIN i[34]
    DIRECTION INPUT ;
    USE SIGNAL ;
    PORT
      LAYER M4 ;
        RECT  23.676 10.128 23.76 10.152 ;
    END
  END i[34]
  PIN i[35]
    DIRECTION INPUT ;
    USE SIGNAL ;
    PORT
      LAYER M4 ;
        RECT  23.676 10.224 23.76 10.248 ;
    END
  END i[35]
  PIN i[36]
    DIRECTION INPUT ;
    USE SIGNAL ;
    PORT
      LAYER M4 ;
        RECT  23.676 10.32 23.76 10.344 ;
    END
  END i[36]
  PIN i[37]
    DIRECTION INPUT ;
    USE SIGNAL ;
    PORT
      LAYER M4 ;
        RECT  23.676 10.416 23.76 10.44 ;
    END
  END i[37]
  PIN i[38]
    DIRECTION INPUT ;
    USE SIGNAL ;
    PORT
      LAYER M4 ;
        RECT  23.676 10.512 23.76 10.536 ;
    END
  END i[38]
  PIN i[39]
    DIRECTION INPUT ;
    USE SIGNAL ;
    PORT
      LAYER M4 ;
        RECT  23.676 10.608 23.76 10.632 ;
    END
  END i[39]
  PIN i[3]
    DIRECTION INPUT ;
    USE SIGNAL ;
    PORT
      LAYER M4 ;
        RECT  23.676 1.008 23.76 1.032 ;
    END
  END i[3]
  PIN i[40]
    DIRECTION INPUT ;
    USE SIGNAL ;
    PORT
      LAYER M4 ;
        RECT  23.676 10.704 23.76 10.728 ;
    END
  END i[40]
  PIN i[41]
    DIRECTION INPUT ;
    USE SIGNAL ;
    PORT
      LAYER M4 ;
        RECT  23.676 10.8 23.76 10.824 ;
    END
  END i[41]
  PIN i[42]
    DIRECTION INPUT ;
    USE SIGNAL ;
    PORT
      LAYER M4 ;
        RECT  23.676 10.896 23.76 10.92 ;
    END
  END i[42]
  PIN i[43]
    DIRECTION INPUT ;
    USE SIGNAL ;
    PORT
      LAYER M4 ;
        RECT  23.676 10.992 23.76 11.016 ;
    END
  END i[43]
  PIN i[44]
    DIRECTION INPUT ;
    USE SIGNAL ;
    PORT
      LAYER M4 ;
        RECT  23.676 11.088 23.76 11.112 ;
    END
  END i[44]
  PIN i[45]
    DIRECTION INPUT ;
    USE SIGNAL ;
    PORT
      LAYER M4 ;
        RECT  23.676 11.184 23.76 11.208 ;
    END
  END i[45]
  PIN i[46]
    DIRECTION INPUT ;
    USE SIGNAL ;
    PORT
      LAYER M4 ;
        RECT  23.676 11.28 23.76 11.304 ;
    END
  END i[46]
  PIN i[47]
    DIRECTION INPUT ;
    USE SIGNAL ;
    PORT
      LAYER M4 ;
        RECT  23.676 11.376 23.76 11.4 ;
    END
  END i[47]
  PIN i[48]
    DIRECTION INPUT ;
    USE SIGNAL ;
    PORT
      LAYER M4 ;
        RECT  23.676 11.472 23.76 11.496 ;
    END
  END i[48]
  PIN i[49]
    DIRECTION INPUT ;
    USE SIGNAL ;
    PORT
      LAYER M4 ;
        RECT  23.676 11.568 23.76 11.592 ;
    END
  END i[49]
  PIN i[4]
    DIRECTION INPUT ;
    USE SIGNAL ;
    PORT
      LAYER M4 ;
        RECT  23.676 1.104 23.76 1.128 ;
    END
  END i[4]
  PIN i[50]
    DIRECTION INPUT ;
    USE SIGNAL ;
    PORT
      LAYER M4 ;
        RECT  23.676 11.664 23.76 11.688 ;
    END
  END i[50]
  PIN i[51]
    DIRECTION INPUT ;
    USE SIGNAL ;
    PORT
      LAYER M4 ;
        RECT  23.676 11.76 23.76 11.784 ;
    END
  END i[51]
  PIN i[52]
    DIRECTION INPUT ;
    USE SIGNAL ;
    PORT
      LAYER M4 ;
        RECT  23.676 11.856 23.76 11.88 ;
    END
  END i[52]
  PIN i[53]
    DIRECTION INPUT ;
    USE SIGNAL ;
    PORT
      LAYER M4 ;
        RECT  23.676 11.952 23.76 11.976 ;
    END
  END i[53]
  PIN i[54]
    DIRECTION INPUT ;
    USE SIGNAL ;
    PORT
      LAYER M4 ;
        RECT  23.676 12.048 23.76 12.072 ;
    END
  END i[54]
  PIN i[55]
    DIRECTION INPUT ;
    USE SIGNAL ;
    PORT
      LAYER M4 ;
        RECT  23.676 12.144 23.76 12.168 ;
    END
  END i[55]
  PIN i[56]
    DIRECTION INPUT ;
    USE SIGNAL ;
    PORT
      LAYER M4 ;
        RECT  23.676 12.24 23.76 12.264 ;
    END
  END i[56]
  PIN i[57]
    DIRECTION INPUT ;
    USE SIGNAL ;
    PORT
      LAYER M4 ;
        RECT  23.676 12.336 23.76 12.36 ;
    END
  END i[57]
  PIN i[58]
    DIRECTION INPUT ;
    USE SIGNAL ;
    PORT
      LAYER M4 ;
        RECT  23.676 12.432 23.76 12.456 ;
    END
  END i[58]
  PIN i[59]
    DIRECTION INPUT ;
    USE SIGNAL ;
    PORT
      LAYER M4 ;
        RECT  23.676 12.528 23.76 12.552 ;
    END
  END i[59]
  PIN i[5]
    DIRECTION INPUT ;
    USE SIGNAL ;
    PORT
      LAYER M4 ;
        RECT  23.676 1.2 23.76 1.224 ;
    END
  END i[5]
  PIN i[60]
    DIRECTION INPUT ;
    USE SIGNAL ;
    PORT
      LAYER M4 ;
        RECT  23.676 12.624 23.76 12.648 ;
    END
  END i[60]
  PIN i[61]
    DIRECTION INPUT ;
    USE SIGNAL ;
    PORT
      LAYER M4 ;
        RECT  23.676 12.72 23.76 12.744 ;
    END
  END i[61]
  PIN i[62]
    DIRECTION INPUT ;
    USE SIGNAL ;
    PORT
      LAYER M4 ;
        RECT  23.676 12.816 23.76 12.84 ;
    END
  END i[62]
  PIN i[63]
    DIRECTION INPUT ;
    USE SIGNAL ;
    PORT
      LAYER M4 ;
        RECT  23.676 12.912 23.76 12.936 ;
    END
  END i[63]
  PIN i[64]
    DIRECTION INPUT ;
    USE SIGNAL ;
    PORT
      LAYER M4 ;
        RECT  23.676 6.864 23.76 6.888 ;
    END
  END i[64]
  PIN i[65]
    DIRECTION INPUT ;
    USE SIGNAL ;
    PORT
      LAYER M4 ;
        RECT  23.676 6.96 23.76 6.984 ;
    END
  END i[65]
  PIN i[66]
    DIRECTION INPUT ;
    USE SIGNAL ;
    PORT
      LAYER M4 ;
        RECT  23.676 7.056 23.76 7.08 ;
    END
  END i[66]
  PIN i[67]
    DIRECTION INPUT ;
    USE SIGNAL ;
    PORT
      LAYER M4 ;
        RECT  23.676 7.152 23.76 7.176 ;
    END
  END i[67]
  PIN i[68]
    DIRECTION INPUT ;
    USE SIGNAL ;
    PORT
      LAYER M4 ;
        RECT  23.676 7.248 23.76 7.272 ;
    END
  END i[68]
  PIN i[69]
    DIRECTION INPUT ;
    USE SIGNAL ;
    PORT
      LAYER M4 ;
        RECT  23.676 7.344 23.76 7.368 ;
    END
  END i[69]
  PIN i[6]
    DIRECTION INPUT ;
    USE SIGNAL ;
    PORT
      LAYER M4 ;
        RECT  23.676 1.296 23.76 1.32 ;
    END
  END i[6]
  PIN i[70]
    DIRECTION INPUT ;
    USE SIGNAL ;
    PORT
      LAYER M4 ;
        RECT  23.676 7.44 23.76 7.464 ;
    END
  END i[70]
  PIN i[71]
    DIRECTION INPUT ;
    USE SIGNAL ;
    PORT
      LAYER M4 ;
        RECT  23.676 7.536 23.76 7.56 ;
    END
  END i[71]
  PIN i[72]
    DIRECTION INPUT ;
    USE SIGNAL ;
    PORT
      LAYER M4 ;
        RECT  23.676 7.632 23.76 7.656 ;
    END
  END i[72]
  PIN i[73]
    DIRECTION INPUT ;
    USE SIGNAL ;
    PORT
      LAYER M4 ;
        RECT  23.676 7.728 23.76 7.752 ;
    END
  END i[73]
  PIN i[74]
    DIRECTION INPUT ;
    USE SIGNAL ;
    PORT
      LAYER M4 ;
        RECT  23.676 7.824 23.76 7.848 ;
    END
  END i[74]
  PIN i[75]
    DIRECTION INPUT ;
    USE SIGNAL ;
    PORT
      LAYER M4 ;
        RECT  23.676 7.92 23.76 7.944 ;
    END
  END i[75]
  PIN i[76]
    DIRECTION INPUT ;
    USE SIGNAL ;
    PORT
      LAYER M4 ;
        RECT  23.676 8.016 23.76 8.04 ;
    END
  END i[76]
  PIN i[77]
    DIRECTION INPUT ;
    USE SIGNAL ;
    PORT
      LAYER M4 ;
        RECT  23.676 8.112 23.76 8.136 ;
    END
  END i[77]
  PIN i[78]
    DIRECTION INPUT ;
    USE SIGNAL ;
    PORT
      LAYER M4 ;
        RECT  23.676 8.208 23.76 8.232 ;
    END
  END i[78]
  PIN i[79]
    DIRECTION INPUT ;
    USE SIGNAL ;
    PORT
      LAYER M4 ;
        RECT  23.676 8.304 23.76 8.328 ;
    END
  END i[79]
  PIN i[7]
    DIRECTION INPUT ;
    USE SIGNAL ;
    PORT
      LAYER M4 ;
        RECT  23.676 1.392 23.76 1.416 ;
    END
  END i[7]
  PIN i[80]
    DIRECTION INPUT ;
    USE SIGNAL ;
    PORT
      LAYER M4 ;
        RECT  23.676 8.4 23.76 8.424 ;
    END
  END i[80]
  PIN i[81]
    DIRECTION INPUT ;
    USE SIGNAL ;
    PORT
      LAYER M4 ;
        RECT  23.676 8.496 23.76 8.52 ;
    END
  END i[81]
  PIN i[82]
    DIRECTION INPUT ;
    USE SIGNAL ;
    PORT
      LAYER M4 ;
        RECT  23.676 8.592 23.76 8.616 ;
    END
  END i[82]
  PIN i[83]
    DIRECTION INPUT ;
    USE SIGNAL ;
    PORT
      LAYER M4 ;
        RECT  23.676 8.688 23.76 8.712 ;
    END
  END i[83]
  PIN i[84]
    DIRECTION INPUT ;
    USE SIGNAL ;
    PORT
      LAYER M4 ;
        RECT  23.676 8.784 23.76 8.808 ;
    END
  END i[84]
  PIN i[85]
    DIRECTION INPUT ;
    USE SIGNAL ;
    PORT
      LAYER M4 ;
        RECT  23.676 8.88 23.76 8.904 ;
    END
  END i[85]
  PIN i[86]
    DIRECTION INPUT ;
    USE SIGNAL ;
    PORT
      LAYER M4 ;
        RECT  23.676 8.976 23.76 9 ;
    END
  END i[86]
  PIN i[87]
    DIRECTION INPUT ;
    USE SIGNAL ;
    PORT
      LAYER M4 ;
        RECT  23.676 9.072 23.76 9.096 ;
    END
  END i[87]
  PIN i[88]
    DIRECTION INPUT ;
    USE SIGNAL ;
    PORT
      LAYER M4 ;
        RECT  23.676 9.168 23.76 9.192 ;
    END
  END i[88]
  PIN i[89]
    DIRECTION INPUT ;
    USE SIGNAL ;
    PORT
      LAYER M4 ;
        RECT  23.676 9.264 23.76 9.288 ;
    END
  END i[89]
  PIN i[8]
    DIRECTION INPUT ;
    USE SIGNAL ;
    PORT
      LAYER M4 ;
        RECT  23.676 1.488 23.76 1.512 ;
    END
  END i[8]
  PIN i[90]
    DIRECTION INPUT ;
    USE SIGNAL ;
    PORT
      LAYER M4 ;
        RECT  23.676 9.36 23.76 9.384 ;
    END
  END i[90]
  PIN i[91]
    DIRECTION INPUT ;
    USE SIGNAL ;
    PORT
      LAYER M4 ;
        RECT  23.676 9.456 23.76 9.48 ;
    END
  END i[91]
  PIN i[92]
    DIRECTION INPUT ;
    USE SIGNAL ;
    PORT
      LAYER M4 ;
        RECT  23.676 9.552 23.76 9.576 ;
    END
  END i[92]
  PIN i[93]
    DIRECTION INPUT ;
    USE SIGNAL ;
    PORT
      LAYER M4 ;
        RECT  23.676 9.648 23.76 9.672 ;
    END
  END i[93]
  PIN i[94]
    DIRECTION INPUT ;
    USE SIGNAL ;
    PORT
      LAYER M4 ;
        RECT  23.676 9.744 23.76 9.768 ;
    END
  END i[94]
  PIN i[95]
    DIRECTION INPUT ;
    USE SIGNAL ;
    PORT
      LAYER M4 ;
        RECT  23.676 9.84 23.76 9.864 ;
    END
  END i[95]
  PIN i[96]
    DIRECTION INPUT ;
    USE SIGNAL ;
    PORT
      LAYER M4 ;
        RECT  23.676 3.792 23.76 3.816 ;
    END
  END i[96]
  PIN i[97]
    DIRECTION INPUT ;
    USE SIGNAL ;
    PORT
      LAYER M4 ;
        RECT  23.676 3.888 23.76 3.912 ;
    END
  END i[97]
  PIN i[98]
    DIRECTION INPUT ;
    USE SIGNAL ;
    PORT
      LAYER M4 ;
        RECT  23.676 3.984 23.76 4.008 ;
    END
  END i[98]
  PIN i[99]
    DIRECTION INPUT ;
    USE SIGNAL ;
    PORT
      LAYER M4 ;
        RECT  23.676 4.08 23.76 4.104 ;
    END
  END i[99]
  PIN i[9]
    DIRECTION INPUT ;
    USE SIGNAL ;
    PORT
      LAYER M4 ;
        RECT  23.676 1.584 23.76 1.608 ;
    END
  END i[9]
  PIN o[0]
    DIRECTION OUTPUT ;
    USE SIGNAL ;
    PORT
      LAYER M4 ;
        RECT  0 20.304 0.084 20.328 ;
    END
  END o[0]
  PIN o[100]
    DIRECTION OUTPUT ;
    USE SIGNAL ;
    PORT
      LAYER M4 ;
        RECT  0 1.488 0.084 1.512 ;
    END
  END o[100]
  PIN o[101]
    DIRECTION OUTPUT ;
    USE SIGNAL ;
    PORT
      LAYER M4 ;
        RECT  0 1.584 0.084 1.608 ;
    END
  END o[101]
  PIN o[102]
    DIRECTION OUTPUT ;
    USE SIGNAL ;
    PORT
      LAYER M4 ;
        RECT  0 1.68 0.084 1.704 ;
    END
  END o[102]
  PIN o[103]
    DIRECTION OUTPUT ;
    USE SIGNAL ;
    PORT
      LAYER M4 ;
        RECT  0 1.776 0.084 1.8 ;
    END
  END o[103]
  PIN o[104]
    DIRECTION OUTPUT ;
    USE SIGNAL ;
    PORT
      LAYER M4 ;
        RECT  0 1.872 0.084 1.896 ;
    END
  END o[104]
  PIN o[105]
    DIRECTION OUTPUT ;
    USE SIGNAL ;
    PORT
      LAYER M4 ;
        RECT  0 1.968 0.084 1.992 ;
    END
  END o[105]
  PIN o[106]
    DIRECTION OUTPUT ;
    USE SIGNAL ;
    PORT
      LAYER M4 ;
        RECT  0 2.064 0.084 2.088 ;
    END
  END o[106]
  PIN o[107]
    DIRECTION OUTPUT ;
    USE SIGNAL ;
    PORT
      LAYER M4 ;
        RECT  0 2.16 0.084 2.184 ;
    END
  END o[107]
  PIN o[108]
    DIRECTION OUTPUT ;
    USE SIGNAL ;
    PORT
      LAYER M4 ;
        RECT  0 2.256 0.084 2.28 ;
    END
  END o[108]
  PIN o[109]
    DIRECTION OUTPUT ;
    USE SIGNAL ;
    PORT
      LAYER M4 ;
        RECT  0 2.352 0.084 2.376 ;
    END
  END o[109]
  PIN o[10]
    DIRECTION OUTPUT ;
    USE SIGNAL ;
    PORT
      LAYER M4 ;
        RECT  0 21.264 0.084 21.288 ;
    END
  END o[10]
  PIN o[110]
    DIRECTION OUTPUT ;
    USE SIGNAL ;
    PORT
      LAYER M4 ;
        RECT  0 2.448 0.084 2.472 ;
    END
  END o[110]
  PIN o[111]
    DIRECTION OUTPUT ;
    USE SIGNAL ;
    PORT
      LAYER M4 ;
        RECT  0 2.544 0.084 2.568 ;
    END
  END o[111]
  PIN o[112]
    DIRECTION OUTPUT ;
    USE SIGNAL ;
    PORT
      LAYER M4 ;
        RECT  0 2.64 0.084 2.664 ;
    END
  END o[112]
  PIN o[113]
    DIRECTION OUTPUT ;
    USE SIGNAL ;
    PORT
      LAYER M4 ;
        RECT  0 2.736 0.084 2.76 ;
    END
  END o[113]
  PIN o[114]
    DIRECTION OUTPUT ;
    USE SIGNAL ;
    PORT
      LAYER M4 ;
        RECT  0 2.832 0.084 2.856 ;
    END
  END o[114]
  PIN o[115]
    DIRECTION OUTPUT ;
    USE SIGNAL ;
    PORT
      LAYER M4 ;
        RECT  0 2.928 0.084 2.952 ;
    END
  END o[115]
  PIN o[116]
    DIRECTION OUTPUT ;
    USE SIGNAL ;
    PORT
      LAYER M4 ;
        RECT  0 3.024 0.084 3.048 ;
    END
  END o[116]
  PIN o[117]
    DIRECTION OUTPUT ;
    USE SIGNAL ;
    PORT
      LAYER M4 ;
        RECT  0 3.12 0.084 3.144 ;
    END
  END o[117]
  PIN o[118]
    DIRECTION OUTPUT ;
    USE SIGNAL ;
    PORT
      LAYER M4 ;
        RECT  0 3.216 0.084 3.24 ;
    END
  END o[118]
  PIN o[119]
    DIRECTION OUTPUT ;
    USE SIGNAL ;
    PORT
      LAYER M4 ;
        RECT  0 3.312 0.084 3.336 ;
    END
  END o[119]
  PIN o[11]
    DIRECTION OUTPUT ;
    USE SIGNAL ;
    PORT
      LAYER M4 ;
        RECT  0 21.36 0.084 21.384 ;
    END
  END o[11]
  PIN o[120]
    DIRECTION OUTPUT ;
    USE SIGNAL ;
    PORT
      LAYER M4 ;
        RECT  0 3.408 0.084 3.432 ;
    END
  END o[120]
  PIN o[121]
    DIRECTION OUTPUT ;
    USE SIGNAL ;
    PORT
      LAYER M4 ;
        RECT  0 3.504 0.084 3.528 ;
    END
  END o[121]
  PIN o[122]
    DIRECTION OUTPUT ;
    USE SIGNAL ;
    PORT
      LAYER M4 ;
        RECT  0 3.6 0.084 3.624 ;
    END
  END o[122]
  PIN o[123]
    DIRECTION OUTPUT ;
    USE SIGNAL ;
    PORT
      LAYER M4 ;
        RECT  0 3.696 0.084 3.72 ;
    END
  END o[123]
  PIN o[124]
    DIRECTION OUTPUT ;
    USE SIGNAL ;
    PORT
      LAYER M4 ;
        RECT  0 3.792 0.084 3.816 ;
    END
  END o[124]
  PIN o[125]
    DIRECTION OUTPUT ;
    USE SIGNAL ;
    PORT
      LAYER M4 ;
        RECT  0 3.888 0.084 3.912 ;
    END
  END o[125]
  PIN o[126]
    DIRECTION OUTPUT ;
    USE SIGNAL ;
    PORT
      LAYER M4 ;
        RECT  0 3.984 0.084 4.008 ;
    END
  END o[126]
  PIN o[127]
    DIRECTION OUTPUT ;
    USE SIGNAL ;
    PORT
      LAYER M4 ;
        RECT  0 4.08 0.084 4.104 ;
    END
  END o[127]
  PIN o[128]
    DIRECTION OUTPUT ;
    USE SIGNAL ;
    PORT
      LAYER M4 ;
        RECT  0 23.376 0.084 23.4 ;
    END
  END o[128]
  PIN o[129]
    DIRECTION OUTPUT ;
    USE SIGNAL ;
    PORT
      LAYER M4 ;
        RECT  0 23.472 0.084 23.496 ;
    END
  END o[129]
  PIN o[12]
    DIRECTION OUTPUT ;
    USE SIGNAL ;
    PORT
      LAYER M4 ;
        RECT  0 21.456 0.084 21.48 ;
    END
  END o[12]
  PIN o[130]
    DIRECTION OUTPUT ;
    USE SIGNAL ;
    PORT
      LAYER M4 ;
        RECT  0 23.568 0.084 23.592 ;
    END
  END o[130]
  PIN o[131]
    DIRECTION OUTPUT ;
    USE SIGNAL ;
    PORT
      LAYER M4 ;
        RECT  0 23.664 0.084 23.688 ;
    END
  END o[131]
  PIN o[132]
    DIRECTION OUTPUT ;
    USE SIGNAL ;
    PORT
      LAYER M4 ;
        RECT  0 23.76 0.084 23.784 ;
    END
  END o[132]
  PIN o[133]
    DIRECTION OUTPUT ;
    USE SIGNAL ;
    PORT
      LAYER M4 ;
        RECT  0 23.856 0.084 23.88 ;
    END
  END o[133]
  PIN o[134]
    DIRECTION OUTPUT ;
    USE SIGNAL ;
    PORT
      LAYER M4 ;
        RECT  0 23.952 0.084 23.976 ;
    END
  END o[134]
  PIN o[135]
    DIRECTION OUTPUT ;
    USE SIGNAL ;
    PORT
      LAYER M4 ;
        RECT  0 24.048 0.084 24.072 ;
    END
  END o[135]
  PIN o[136]
    DIRECTION OUTPUT ;
    USE SIGNAL ;
    PORT
      LAYER M4 ;
        RECT  0 24.144 0.084 24.168 ;
    END
  END o[136]
  PIN o[137]
    DIRECTION OUTPUT ;
    USE SIGNAL ;
    PORT
      LAYER M4 ;
        RECT  0 24.24 0.084 24.264 ;
    END
  END o[137]
  PIN o[138]
    DIRECTION OUTPUT ;
    USE SIGNAL ;
    PORT
      LAYER M4 ;
        RECT  0 24.336 0.084 24.36 ;
    END
  END o[138]
  PIN o[139]
    DIRECTION OUTPUT ;
    USE SIGNAL ;
    PORT
      LAYER M4 ;
        RECT  0 24.432 0.084 24.456 ;
    END
  END o[139]
  PIN o[13]
    DIRECTION OUTPUT ;
    USE SIGNAL ;
    PORT
      LAYER M4 ;
        RECT  0 21.552 0.084 21.576 ;
    END
  END o[13]
  PIN o[140]
    DIRECTION OUTPUT ;
    USE SIGNAL ;
    PORT
      LAYER M4 ;
        RECT  0 24.528 0.084 24.552 ;
    END
  END o[140]
  PIN o[141]
    DIRECTION OUTPUT ;
    USE SIGNAL ;
    PORT
      LAYER M4 ;
        RECT  0 24.624 0.084 24.648 ;
    END
  END o[141]
  PIN o[142]
    DIRECTION OUTPUT ;
    USE SIGNAL ;
    PORT
      LAYER M4 ;
        RECT  0 24.72 0.084 24.744 ;
    END
  END o[142]
  PIN o[143]
    DIRECTION OUTPUT ;
    USE SIGNAL ;
    PORT
      LAYER M4 ;
        RECT  0 24.816 0.084 24.84 ;
    END
  END o[143]
  PIN o[144]
    DIRECTION OUTPUT ;
    USE SIGNAL ;
    PORT
      LAYER M4 ;
        RECT  0 24.912 0.084 24.936 ;
    END
  END o[144]
  PIN o[145]
    DIRECTION OUTPUT ;
    USE SIGNAL ;
    PORT
      LAYER M4 ;
        RECT  0 25.008 0.084 25.032 ;
    END
  END o[145]
  PIN o[146]
    DIRECTION OUTPUT ;
    USE SIGNAL ;
    PORT
      LAYER M4 ;
        RECT  0 25.104 0.084 25.128 ;
    END
  END o[146]
  PIN o[147]
    DIRECTION OUTPUT ;
    USE SIGNAL ;
    PORT
      LAYER M4 ;
        RECT  0 25.2 0.084 25.224 ;
    END
  END o[147]
  PIN o[148]
    DIRECTION OUTPUT ;
    USE SIGNAL ;
    PORT
      LAYER M4 ;
        RECT  0 25.296 0.084 25.32 ;
    END
  END o[148]
  PIN o[149]
    DIRECTION OUTPUT ;
    USE SIGNAL ;
    PORT
      LAYER M4 ;
        RECT  0 25.392 0.084 25.416 ;
    END
  END o[149]
  PIN o[14]
    DIRECTION OUTPUT ;
    USE SIGNAL ;
    PORT
      LAYER M4 ;
        RECT  0 21.648 0.084 21.672 ;
    END
  END o[14]
  PIN o[150]
    DIRECTION OUTPUT ;
    USE SIGNAL ;
    PORT
      LAYER M4 ;
        RECT  0 25.488 0.084 25.512 ;
    END
  END o[150]
  PIN o[151]
    DIRECTION OUTPUT ;
    USE SIGNAL ;
    PORT
      LAYER M4 ;
        RECT  0 25.584 0.084 25.608 ;
    END
  END o[151]
  PIN o[152]
    DIRECTION OUTPUT ;
    USE SIGNAL ;
    PORT
      LAYER M4 ;
        RECT  0 25.68 0.084 25.704 ;
    END
  END o[152]
  PIN o[153]
    DIRECTION OUTPUT ;
    USE SIGNAL ;
    PORT
      LAYER M4 ;
        RECT  0 25.776 0.084 25.8 ;
    END
  END o[153]
  PIN o[154]
    DIRECTION OUTPUT ;
    USE SIGNAL ;
    PORT
      LAYER M4 ;
        RECT  0 25.872 0.084 25.896 ;
    END
  END o[154]
  PIN o[155]
    DIRECTION OUTPUT ;
    USE SIGNAL ;
    PORT
      LAYER M4 ;
        RECT  0 25.968 0.084 25.992 ;
    END
  END o[155]
  PIN o[156]
    DIRECTION OUTPUT ;
    USE SIGNAL ;
    PORT
      LAYER M4 ;
        RECT  0 26.064 0.084 26.088 ;
    END
  END o[156]
  PIN o[157]
    DIRECTION OUTPUT ;
    USE SIGNAL ;
    PORT
      LAYER M4 ;
        RECT  0 26.16 0.084 26.184 ;
    END
  END o[157]
  PIN o[158]
    DIRECTION OUTPUT ;
    USE SIGNAL ;
    PORT
      LAYER M4 ;
        RECT  0 26.256 0.084 26.28 ;
    END
  END o[158]
  PIN o[159]
    DIRECTION OUTPUT ;
    USE SIGNAL ;
    PORT
      LAYER M4 ;
        RECT  0 26.352 0.084 26.376 ;
    END
  END o[159]
  PIN o[15]
    DIRECTION OUTPUT ;
    USE SIGNAL ;
    PORT
      LAYER M4 ;
        RECT  0 21.744 0.084 21.768 ;
    END
  END o[15]
  PIN o[160]
    DIRECTION OUTPUT ;
    USE SIGNAL ;
    PORT
      LAYER M4 ;
        RECT  0 17.232 0.084 17.256 ;
    END
  END o[160]
  PIN o[161]
    DIRECTION OUTPUT ;
    USE SIGNAL ;
    PORT
      LAYER M4 ;
        RECT  0 17.328 0.084 17.352 ;
    END
  END o[161]
  PIN o[162]
    DIRECTION OUTPUT ;
    USE SIGNAL ;
    PORT
      LAYER M4 ;
        RECT  0 17.424 0.084 17.448 ;
    END
  END o[162]
  PIN o[163]
    DIRECTION OUTPUT ;
    USE SIGNAL ;
    PORT
      LAYER M4 ;
        RECT  0 17.52 0.084 17.544 ;
    END
  END o[163]
  PIN o[164]
    DIRECTION OUTPUT ;
    USE SIGNAL ;
    PORT
      LAYER M4 ;
        RECT  0 17.616 0.084 17.64 ;
    END
  END o[164]
  PIN o[165]
    DIRECTION OUTPUT ;
    USE SIGNAL ;
    PORT
      LAYER M4 ;
        RECT  0 17.712 0.084 17.736 ;
    END
  END o[165]
  PIN o[166]
    DIRECTION OUTPUT ;
    USE SIGNAL ;
    PORT
      LAYER M4 ;
        RECT  0 17.808 0.084 17.832 ;
    END
  END o[166]
  PIN o[167]
    DIRECTION OUTPUT ;
    USE SIGNAL ;
    PORT
      LAYER M4 ;
        RECT  0 17.904 0.084 17.928 ;
    END
  END o[167]
  PIN o[168]
    DIRECTION OUTPUT ;
    USE SIGNAL ;
    PORT
      LAYER M4 ;
        RECT  0 18 0.084 18.024 ;
    END
  END o[168]
  PIN o[169]
    DIRECTION OUTPUT ;
    USE SIGNAL ;
    PORT
      LAYER M4 ;
        RECT  0 18.096 0.084 18.12 ;
    END
  END o[169]
  PIN o[16]
    DIRECTION OUTPUT ;
    USE SIGNAL ;
    PORT
      LAYER M4 ;
        RECT  0 21.84 0.084 21.864 ;
    END
  END o[16]
  PIN o[170]
    DIRECTION OUTPUT ;
    USE SIGNAL ;
    PORT
      LAYER M4 ;
        RECT  0 18.192 0.084 18.216 ;
    END
  END o[170]
  PIN o[171]
    DIRECTION OUTPUT ;
    USE SIGNAL ;
    PORT
      LAYER M4 ;
        RECT  0 18.288 0.084 18.312 ;
    END
  END o[171]
  PIN o[172]
    DIRECTION OUTPUT ;
    USE SIGNAL ;
    PORT
      LAYER M4 ;
        RECT  0 18.384 0.084 18.408 ;
    END
  END o[172]
  PIN o[173]
    DIRECTION OUTPUT ;
    USE SIGNAL ;
    PORT
      LAYER M4 ;
        RECT  0 18.48 0.084 18.504 ;
    END
  END o[173]
  PIN o[174]
    DIRECTION OUTPUT ;
    USE SIGNAL ;
    PORT
      LAYER M4 ;
        RECT  0 18.576 0.084 18.6 ;
    END
  END o[174]
  PIN o[175]
    DIRECTION OUTPUT ;
    USE SIGNAL ;
    PORT
      LAYER M4 ;
        RECT  0 18.672 0.084 18.696 ;
    END
  END o[175]
  PIN o[176]
    DIRECTION OUTPUT ;
    USE SIGNAL ;
    PORT
      LAYER M4 ;
        RECT  0 18.768 0.084 18.792 ;
    END
  END o[176]
  PIN o[177]
    DIRECTION OUTPUT ;
    USE SIGNAL ;
    PORT
      LAYER M4 ;
        RECT  0 18.864 0.084 18.888 ;
    END
  END o[177]
  PIN o[178]
    DIRECTION OUTPUT ;
    USE SIGNAL ;
    PORT
      LAYER M4 ;
        RECT  0 18.96 0.084 18.984 ;
    END
  END o[178]
  PIN o[179]
    DIRECTION OUTPUT ;
    USE SIGNAL ;
    PORT
      LAYER M4 ;
        RECT  0 19.056 0.084 19.08 ;
    END
  END o[179]
  PIN o[17]
    DIRECTION OUTPUT ;
    USE SIGNAL ;
    PORT
      LAYER M4 ;
        RECT  0 21.936 0.084 21.96 ;
    END
  END o[17]
  PIN o[180]
    DIRECTION OUTPUT ;
    USE SIGNAL ;
    PORT
      LAYER M4 ;
        RECT  0 19.152 0.084 19.176 ;
    END
  END o[180]
  PIN o[181]
    DIRECTION OUTPUT ;
    USE SIGNAL ;
    PORT
      LAYER M4 ;
        RECT  0 19.248 0.084 19.272 ;
    END
  END o[181]
  PIN o[182]
    DIRECTION OUTPUT ;
    USE SIGNAL ;
    PORT
      LAYER M4 ;
        RECT  0 19.344 0.084 19.368 ;
    END
  END o[182]
  PIN o[183]
    DIRECTION OUTPUT ;
    USE SIGNAL ;
    PORT
      LAYER M4 ;
        RECT  0 19.44 0.084 19.464 ;
    END
  END o[183]
  PIN o[184]
    DIRECTION OUTPUT ;
    USE SIGNAL ;
    PORT
      LAYER M4 ;
        RECT  0 19.536 0.084 19.56 ;
    END
  END o[184]
  PIN o[185]
    DIRECTION OUTPUT ;
    USE SIGNAL ;
    PORT
      LAYER M4 ;
        RECT  0 19.632 0.084 19.656 ;
    END
  END o[185]
  PIN o[186]
    DIRECTION OUTPUT ;
    USE SIGNAL ;
    PORT
      LAYER M4 ;
        RECT  0 19.728 0.084 19.752 ;
    END
  END o[186]
  PIN o[187]
    DIRECTION OUTPUT ;
    USE SIGNAL ;
    PORT
      LAYER M4 ;
        RECT  0 19.824 0.084 19.848 ;
    END
  END o[187]
  PIN o[188]
    DIRECTION OUTPUT ;
    USE SIGNAL ;
    PORT
      LAYER M4 ;
        RECT  0 19.92 0.084 19.944 ;
    END
  END o[188]
  PIN o[189]
    DIRECTION OUTPUT ;
    USE SIGNAL ;
    PORT
      LAYER M4 ;
        RECT  0 20.016 0.084 20.04 ;
    END
  END o[189]
  PIN o[18]
    DIRECTION OUTPUT ;
    USE SIGNAL ;
    PORT
      LAYER M4 ;
        RECT  0 22.032 0.084 22.056 ;
    END
  END o[18]
  PIN o[190]
    DIRECTION OUTPUT ;
    USE SIGNAL ;
    PORT
      LAYER M4 ;
        RECT  0 20.112 0.084 20.136 ;
    END
  END o[190]
  PIN o[191]
    DIRECTION OUTPUT ;
    USE SIGNAL ;
    PORT
      LAYER M4 ;
        RECT  0 20.208 0.084 20.232 ;
    END
  END o[191]
  PIN o[192]
    DIRECTION OUTPUT ;
    USE SIGNAL ;
    PORT
      LAYER M4 ;
        RECT  0 14.16 0.084 14.184 ;
    END
  END o[192]
  PIN o[193]
    DIRECTION OUTPUT ;
    USE SIGNAL ;
    PORT
      LAYER M4 ;
        RECT  0 14.256 0.084 14.28 ;
    END
  END o[193]
  PIN o[194]
    DIRECTION OUTPUT ;
    USE SIGNAL ;
    PORT
      LAYER M4 ;
        RECT  0 14.352 0.084 14.376 ;
    END
  END o[194]
  PIN o[195]
    DIRECTION OUTPUT ;
    USE SIGNAL ;
    PORT
      LAYER M4 ;
        RECT  0 14.448 0.084 14.472 ;
    END
  END o[195]
  PIN o[196]
    DIRECTION OUTPUT ;
    USE SIGNAL ;
    PORT
      LAYER M4 ;
        RECT  0 14.544 0.084 14.568 ;
    END
  END o[196]
  PIN o[197]
    DIRECTION OUTPUT ;
    USE SIGNAL ;
    PORT
      LAYER M4 ;
        RECT  0 14.64 0.084 14.664 ;
    END
  END o[197]
  PIN o[198]
    DIRECTION OUTPUT ;
    USE SIGNAL ;
    PORT
      LAYER M4 ;
        RECT  0 14.736 0.084 14.76 ;
    END
  END o[198]
  PIN o[199]
    DIRECTION OUTPUT ;
    USE SIGNAL ;
    PORT
      LAYER M4 ;
        RECT  0 14.832 0.084 14.856 ;
    END
  END o[199]
  PIN o[19]
    DIRECTION OUTPUT ;
    USE SIGNAL ;
    PORT
      LAYER M4 ;
        RECT  0 22.128 0.084 22.152 ;
    END
  END o[19]
  PIN o[1]
    DIRECTION OUTPUT ;
    USE SIGNAL ;
    PORT
      LAYER M4 ;
        RECT  0 20.4 0.084 20.424 ;
    END
  END o[1]
  PIN o[200]
    DIRECTION OUTPUT ;
    USE SIGNAL ;
    PORT
      LAYER M4 ;
        RECT  0 14.928 0.084 14.952 ;
    END
  END o[200]
  PIN o[201]
    DIRECTION OUTPUT ;
    USE SIGNAL ;
    PORT
      LAYER M4 ;
        RECT  0 15.024 0.084 15.048 ;
    END
  END o[201]
  PIN o[202]
    DIRECTION OUTPUT ;
    USE SIGNAL ;
    PORT
      LAYER M4 ;
        RECT  0 15.12 0.084 15.144 ;
    END
  END o[202]
  PIN o[203]
    DIRECTION OUTPUT ;
    USE SIGNAL ;
    PORT
      LAYER M4 ;
        RECT  0 15.216 0.084 15.24 ;
    END
  END o[203]
  PIN o[204]
    DIRECTION OUTPUT ;
    USE SIGNAL ;
    PORT
      LAYER M4 ;
        RECT  0 15.312 0.084 15.336 ;
    END
  END o[204]
  PIN o[205]
    DIRECTION OUTPUT ;
    USE SIGNAL ;
    PORT
      LAYER M4 ;
        RECT  0 15.408 0.084 15.432 ;
    END
  END o[205]
  PIN o[206]
    DIRECTION OUTPUT ;
    USE SIGNAL ;
    PORT
      LAYER M4 ;
        RECT  0 15.504 0.084 15.528 ;
    END
  END o[206]
  PIN o[207]
    DIRECTION OUTPUT ;
    USE SIGNAL ;
    PORT
      LAYER M4 ;
        RECT  0 15.6 0.084 15.624 ;
    END
  END o[207]
  PIN o[208]
    DIRECTION OUTPUT ;
    USE SIGNAL ;
    PORT
      LAYER M4 ;
        RECT  0 15.696 0.084 15.72 ;
    END
  END o[208]
  PIN o[209]
    DIRECTION OUTPUT ;
    USE SIGNAL ;
    PORT
      LAYER M4 ;
        RECT  0 15.792 0.084 15.816 ;
    END
  END o[209]
  PIN o[20]
    DIRECTION OUTPUT ;
    USE SIGNAL ;
    PORT
      LAYER M4 ;
        RECT  0 22.224 0.084 22.248 ;
    END
  END o[20]
  PIN o[210]
    DIRECTION OUTPUT ;
    USE SIGNAL ;
    PORT
      LAYER M4 ;
        RECT  0 15.888 0.084 15.912 ;
    END
  END o[210]
  PIN o[211]
    DIRECTION OUTPUT ;
    USE SIGNAL ;
    PORT
      LAYER M4 ;
        RECT  0 15.984 0.084 16.008 ;
    END
  END o[211]
  PIN o[212]
    DIRECTION OUTPUT ;
    USE SIGNAL ;
    PORT
      LAYER M4 ;
        RECT  0 16.08 0.084 16.104 ;
    END
  END o[212]
  PIN o[213]
    DIRECTION OUTPUT ;
    USE SIGNAL ;
    PORT
      LAYER M4 ;
        RECT  0 16.176 0.084 16.2 ;
    END
  END o[213]
  PIN o[214]
    DIRECTION OUTPUT ;
    USE SIGNAL ;
    PORT
      LAYER M4 ;
        RECT  0 16.272 0.084 16.296 ;
    END
  END o[214]
  PIN o[215]
    DIRECTION OUTPUT ;
    USE SIGNAL ;
    PORT
      LAYER M4 ;
        RECT  0 16.368 0.084 16.392 ;
    END
  END o[215]
  PIN o[216]
    DIRECTION OUTPUT ;
    USE SIGNAL ;
    PORT
      LAYER M4 ;
        RECT  0 16.464 0.084 16.488 ;
    END
  END o[216]
  PIN o[217]
    DIRECTION OUTPUT ;
    USE SIGNAL ;
    PORT
      LAYER M4 ;
        RECT  0 16.56 0.084 16.584 ;
    END
  END o[217]
  PIN o[218]
    DIRECTION OUTPUT ;
    USE SIGNAL ;
    PORT
      LAYER M4 ;
        RECT  0 16.656 0.084 16.68 ;
    END
  END o[218]
  PIN o[219]
    DIRECTION OUTPUT ;
    USE SIGNAL ;
    PORT
      LAYER M4 ;
        RECT  0 16.752 0.084 16.776 ;
    END
  END o[219]
  PIN o[21]
    DIRECTION OUTPUT ;
    USE SIGNAL ;
    PORT
      LAYER M4 ;
        RECT  0 22.32 0.084 22.344 ;
    END
  END o[21]
  PIN o[220]
    DIRECTION OUTPUT ;
    USE SIGNAL ;
    PORT
      LAYER M4 ;
        RECT  0 16.848 0.084 16.872 ;
    END
  END o[220]
  PIN o[221]
    DIRECTION OUTPUT ;
    USE SIGNAL ;
    PORT
      LAYER M4 ;
        RECT  0 16.944 0.084 16.968 ;
    END
  END o[221]
  PIN o[222]
    DIRECTION OUTPUT ;
    USE SIGNAL ;
    PORT
      LAYER M4 ;
        RECT  0 17.04 0.084 17.064 ;
    END
  END o[222]
  PIN o[223]
    DIRECTION OUTPUT ;
    USE SIGNAL ;
    PORT
      LAYER M4 ;
        RECT  0 17.136 0.084 17.16 ;
    END
  END o[223]
  PIN o[224]
    DIRECTION OUTPUT ;
    USE SIGNAL ;
    PORT
      LAYER M4 ;
        RECT  0 4.176 0.084 4.2 ;
    END
  END o[224]
  PIN o[225]
    DIRECTION OUTPUT ;
    USE SIGNAL ;
    PORT
      LAYER M4 ;
        RECT  0 4.272 0.084 4.296 ;
    END
  END o[225]
  PIN o[226]
    DIRECTION OUTPUT ;
    USE SIGNAL ;
    PORT
      LAYER M4 ;
        RECT  0 4.368 0.084 4.392 ;
    END
  END o[226]
  PIN o[227]
    DIRECTION OUTPUT ;
    USE SIGNAL ;
    PORT
      LAYER M4 ;
        RECT  0 4.464 0.084 4.488 ;
    END
  END o[227]
  PIN o[228]
    DIRECTION OUTPUT ;
    USE SIGNAL ;
    PORT
      LAYER M4 ;
        RECT  0 4.56 0.084 4.584 ;
    END
  END o[228]
  PIN o[229]
    DIRECTION OUTPUT ;
    USE SIGNAL ;
    PORT
      LAYER M4 ;
        RECT  0 4.656 0.084 4.68 ;
    END
  END o[229]
  PIN o[22]
    DIRECTION OUTPUT ;
    USE SIGNAL ;
    PORT
      LAYER M4 ;
        RECT  0 22.416 0.084 22.44 ;
    END
  END o[22]
  PIN o[230]
    DIRECTION OUTPUT ;
    USE SIGNAL ;
    PORT
      LAYER M4 ;
        RECT  0 4.752 0.084 4.776 ;
    END
  END o[230]
  PIN o[231]
    DIRECTION OUTPUT ;
    USE SIGNAL ;
    PORT
      LAYER M4 ;
        RECT  0 4.848 0.084 4.872 ;
    END
  END o[231]
  PIN o[232]
    DIRECTION OUTPUT ;
    USE SIGNAL ;
    PORT
      LAYER M4 ;
        RECT  0 4.944 0.084 4.968 ;
    END
  END o[232]
  PIN o[233]
    DIRECTION OUTPUT ;
    USE SIGNAL ;
    PORT
      LAYER M4 ;
        RECT  0 5.04 0.084 5.064 ;
    END
  END o[233]
  PIN o[234]
    DIRECTION OUTPUT ;
    USE SIGNAL ;
    PORT
      LAYER M4 ;
        RECT  0 5.136 0.084 5.16 ;
    END
  END o[234]
  PIN o[235]
    DIRECTION OUTPUT ;
    USE SIGNAL ;
    PORT
      LAYER M4 ;
        RECT  0 5.232 0.084 5.256 ;
    END
  END o[235]
  PIN o[236]
    DIRECTION OUTPUT ;
    USE SIGNAL ;
    PORT
      LAYER M4 ;
        RECT  0 5.328 0.084 5.352 ;
    END
  END o[236]
  PIN o[237]
    DIRECTION OUTPUT ;
    USE SIGNAL ;
    PORT
      LAYER M4 ;
        RECT  0 5.424 0.084 5.448 ;
    END
  END o[237]
  PIN o[238]
    DIRECTION OUTPUT ;
    USE SIGNAL ;
    PORT
      LAYER M4 ;
        RECT  0 5.52 0.084 5.544 ;
    END
  END o[238]
  PIN o[239]
    DIRECTION OUTPUT ;
    USE SIGNAL ;
    PORT
      LAYER M4 ;
        RECT  0 5.616 0.084 5.64 ;
    END
  END o[239]
  PIN o[23]
    DIRECTION OUTPUT ;
    USE SIGNAL ;
    PORT
      LAYER M4 ;
        RECT  0 22.512 0.084 22.536 ;
    END
  END o[23]
  PIN o[240]
    DIRECTION OUTPUT ;
    USE SIGNAL ;
    PORT
      LAYER M4 ;
        RECT  0 5.712 0.084 5.736 ;
    END
  END o[240]
  PIN o[241]
    DIRECTION OUTPUT ;
    USE SIGNAL ;
    PORT
      LAYER M4 ;
        RECT  0 5.808 0.084 5.832 ;
    END
  END o[241]
  PIN o[242]
    DIRECTION OUTPUT ;
    USE SIGNAL ;
    PORT
      LAYER M4 ;
        RECT  0 5.904 0.084 5.928 ;
    END
  END o[242]
  PIN o[243]
    DIRECTION OUTPUT ;
    USE SIGNAL ;
    PORT
      LAYER M4 ;
        RECT  0 6 0.084 6.024 ;
    END
  END o[243]
  PIN o[244]
    DIRECTION OUTPUT ;
    USE SIGNAL ;
    PORT
      LAYER M4 ;
        RECT  0 6.096 0.084 6.12 ;
    END
  END o[244]
  PIN o[245]
    DIRECTION OUTPUT ;
    USE SIGNAL ;
    PORT
      LAYER M4 ;
        RECT  0 6.192 0.084 6.216 ;
    END
  END o[245]
  PIN o[246]
    DIRECTION OUTPUT ;
    USE SIGNAL ;
    PORT
      LAYER M4 ;
        RECT  0 6.288 0.084 6.312 ;
    END
  END o[246]
  PIN o[247]
    DIRECTION OUTPUT ;
    USE SIGNAL ;
    PORT
      LAYER M4 ;
        RECT  0 6.384 0.084 6.408 ;
    END
  END o[247]
  PIN o[248]
    DIRECTION OUTPUT ;
    USE SIGNAL ;
    PORT
      LAYER M4 ;
        RECT  0 6.48 0.084 6.504 ;
    END
  END o[248]
  PIN o[249]
    DIRECTION OUTPUT ;
    USE SIGNAL ;
    PORT
      LAYER M4 ;
        RECT  0 6.576 0.084 6.6 ;
    END
  END o[249]
  PIN o[24]
    DIRECTION OUTPUT ;
    USE SIGNAL ;
    PORT
      LAYER M4 ;
        RECT  0 22.608 0.084 22.632 ;
    END
  END o[24]
  PIN o[250]
    DIRECTION OUTPUT ;
    USE SIGNAL ;
    PORT
      LAYER M4 ;
        RECT  0 6.672 0.084 6.696 ;
    END
  END o[250]
  PIN o[251]
    DIRECTION OUTPUT ;
    USE SIGNAL ;
    PORT
      LAYER M4 ;
        RECT  0 6.768 0.084 6.792 ;
    END
  END o[251]
  PIN o[252]
    DIRECTION OUTPUT ;
    USE SIGNAL ;
    PORT
      LAYER M4 ;
        RECT  0 6.864 0.084 6.888 ;
    END
  END o[252]
  PIN o[253]
    DIRECTION OUTPUT ;
    USE SIGNAL ;
    PORT
      LAYER M4 ;
        RECT  0 6.96 0.084 6.984 ;
    END
  END o[253]
  PIN o[254]
    DIRECTION OUTPUT ;
    USE SIGNAL ;
    PORT
      LAYER M4 ;
        RECT  0 7.056 0.084 7.08 ;
    END
  END o[254]
  PIN o[255]
    DIRECTION OUTPUT ;
    USE SIGNAL ;
    PORT
      LAYER M4 ;
        RECT  0 7.152 0.084 7.176 ;
    END
  END o[255]
  PIN o[256]
    DIRECTION OUTPUT ;
    USE SIGNAL ;
    PORT
      LAYER M4 ;
        RECT  0 7.728 0.084 7.752 ;
    END
  END o[256]
  PIN o[257]
    DIRECTION OUTPUT ;
    USE SIGNAL ;
    PORT
      LAYER M4 ;
        RECT  0 7.824 0.084 7.848 ;
    END
  END o[257]
  PIN o[258]
    DIRECTION OUTPUT ;
    USE SIGNAL ;
    PORT
      LAYER M4 ;
        RECT  0 7.92 0.084 7.944 ;
    END
  END o[258]
  PIN o[259]
    DIRECTION OUTPUT ;
    USE SIGNAL ;
    PORT
      LAYER M4 ;
        RECT  0 8.016 0.084 8.04 ;
    END
  END o[259]
  PIN o[25]
    DIRECTION OUTPUT ;
    USE SIGNAL ;
    PORT
      LAYER M4 ;
        RECT  0 22.704 0.084 22.728 ;
    END
  END o[25]
  PIN o[260]
    DIRECTION OUTPUT ;
    USE SIGNAL ;
    PORT
      LAYER M4 ;
        RECT  0 8.112 0.084 8.136 ;
    END
  END o[260]
  PIN o[261]
    DIRECTION OUTPUT ;
    USE SIGNAL ;
    PORT
      LAYER M4 ;
        RECT  0 8.208 0.084 8.232 ;
    END
  END o[261]
  PIN o[262]
    DIRECTION OUTPUT ;
    USE SIGNAL ;
    PORT
      LAYER M4 ;
        RECT  0 8.304 0.084 8.328 ;
    END
  END o[262]
  PIN o[263]
    DIRECTION OUTPUT ;
    USE SIGNAL ;
    PORT
      LAYER M4 ;
        RECT  0 8.4 0.084 8.424 ;
    END
  END o[263]
  PIN o[264]
    DIRECTION OUTPUT ;
    USE SIGNAL ;
    PORT
      LAYER M4 ;
        RECT  0 8.496 0.084 8.52 ;
    END
  END o[264]
  PIN o[265]
    DIRECTION OUTPUT ;
    USE SIGNAL ;
    PORT
      LAYER M4 ;
        RECT  0 8.592 0.084 8.616 ;
    END
  END o[265]
  PIN o[266]
    DIRECTION OUTPUT ;
    USE SIGNAL ;
    PORT
      LAYER M4 ;
        RECT  0 8.688 0.084 8.712 ;
    END
  END o[266]
  PIN o[267]
    DIRECTION OUTPUT ;
    USE SIGNAL ;
    PORT
      LAYER M4 ;
        RECT  0 8.784 0.084 8.808 ;
    END
  END o[267]
  PIN o[268]
    DIRECTION OUTPUT ;
    USE SIGNAL ;
    PORT
      LAYER M4 ;
        RECT  0 8.88 0.084 8.904 ;
    END
  END o[268]
  PIN o[269]
    DIRECTION OUTPUT ;
    USE SIGNAL ;
    PORT
      LAYER M4 ;
        RECT  0 8.976 0.084 9 ;
    END
  END o[269]
  PIN o[26]
    DIRECTION OUTPUT ;
    USE SIGNAL ;
    PORT
      LAYER M4 ;
        RECT  0 22.8 0.084 22.824 ;
    END
  END o[26]
  PIN o[270]
    DIRECTION OUTPUT ;
    USE SIGNAL ;
    PORT
      LAYER M4 ;
        RECT  0 9.072 0.084 9.096 ;
    END
  END o[270]
  PIN o[271]
    DIRECTION OUTPUT ;
    USE SIGNAL ;
    PORT
      LAYER M4 ;
        RECT  0 9.168 0.084 9.192 ;
    END
  END o[271]
  PIN o[272]
    DIRECTION OUTPUT ;
    USE SIGNAL ;
    PORT
      LAYER M4 ;
        RECT  0 9.264 0.084 9.288 ;
    END
  END o[272]
  PIN o[273]
    DIRECTION OUTPUT ;
    USE SIGNAL ;
    PORT
      LAYER M4 ;
        RECT  0 9.36 0.084 9.384 ;
    END
  END o[273]
  PIN o[274]
    DIRECTION OUTPUT ;
    USE SIGNAL ;
    PORT
      LAYER M4 ;
        RECT  0 9.456 0.084 9.48 ;
    END
  END o[274]
  PIN o[275]
    DIRECTION OUTPUT ;
    USE SIGNAL ;
    PORT
      LAYER M4 ;
        RECT  0 9.552 0.084 9.576 ;
    END
  END o[275]
  PIN o[276]
    DIRECTION OUTPUT ;
    USE SIGNAL ;
    PORT
      LAYER M4 ;
        RECT  0 9.648 0.084 9.672 ;
    END
  END o[276]
  PIN o[277]
    DIRECTION OUTPUT ;
    USE SIGNAL ;
    PORT
      LAYER M4 ;
        RECT  0 9.744 0.084 9.768 ;
    END
  END o[277]
  PIN o[278]
    DIRECTION OUTPUT ;
    USE SIGNAL ;
    PORT
      LAYER M4 ;
        RECT  0 9.84 0.084 9.864 ;
    END
  END o[278]
  PIN o[279]
    DIRECTION OUTPUT ;
    USE SIGNAL ;
    PORT
      LAYER M4 ;
        RECT  0 9.936 0.084 9.96 ;
    END
  END o[279]
  PIN o[27]
    DIRECTION OUTPUT ;
    USE SIGNAL ;
    PORT
      LAYER M4 ;
        RECT  0 22.896 0.084 22.92 ;
    END
  END o[27]
  PIN o[280]
    DIRECTION OUTPUT ;
    USE SIGNAL ;
    PORT
      LAYER M4 ;
        RECT  0 10.032 0.084 10.056 ;
    END
  END o[280]
  PIN o[281]
    DIRECTION OUTPUT ;
    USE SIGNAL ;
    PORT
      LAYER M4 ;
        RECT  0 10.128 0.084 10.152 ;
    END
  END o[281]
  PIN o[282]
    DIRECTION OUTPUT ;
    USE SIGNAL ;
    PORT
      LAYER M4 ;
        RECT  0 10.224 0.084 10.248 ;
    END
  END o[282]
  PIN o[28]
    DIRECTION OUTPUT ;
    USE SIGNAL ;
    PORT
      LAYER M4 ;
        RECT  0 22.992 0.084 23.016 ;
    END
  END o[28]
  PIN o[29]
    DIRECTION OUTPUT ;
    USE SIGNAL ;
    PORT
      LAYER M4 ;
        RECT  0 23.088 0.084 23.112 ;
    END
  END o[29]
  PIN o[2]
    DIRECTION OUTPUT ;
    USE SIGNAL ;
    PORT
      LAYER M4 ;
        RECT  0 20.496 0.084 20.52 ;
    END
  END o[2]
  PIN o[30]
    DIRECTION OUTPUT ;
    USE SIGNAL ;
    PORT
      LAYER M4 ;
        RECT  0 23.184 0.084 23.208 ;
    END
  END o[30]
  PIN o[31]
    DIRECTION OUTPUT ;
    USE SIGNAL ;
    PORT
      LAYER M4 ;
        RECT  0 23.28 0.084 23.304 ;
    END
  END o[31]
  PIN o[32]
    DIRECTION OUTPUT ;
    USE SIGNAL ;
    PORT
      LAYER M4 ;
        RECT  0 26.448 0.084 26.472 ;
    END
  END o[32]
  PIN o[33]
    DIRECTION OUTPUT ;
    USE SIGNAL ;
    PORT
      LAYER M4 ;
        RECT  0 26.544 0.084 26.568 ;
    END
  END o[33]
  PIN o[34]
    DIRECTION OUTPUT ;
    USE SIGNAL ;
    PORT
      LAYER M4 ;
        RECT  0 26.64 0.084 26.664 ;
    END
  END o[34]
  PIN o[35]
    DIRECTION OUTPUT ;
    USE SIGNAL ;
    PORT
      LAYER M4 ;
        RECT  0 26.736 0.084 26.76 ;
    END
  END o[35]
  PIN o[36]
    DIRECTION OUTPUT ;
    USE SIGNAL ;
    PORT
      LAYER M4 ;
        RECT  0 26.832 0.084 26.856 ;
    END
  END o[36]
  PIN o[37]
    DIRECTION OUTPUT ;
    USE SIGNAL ;
    PORT
      LAYER M4 ;
        RECT  0 26.928 0.084 26.952 ;
    END
  END o[37]
  PIN o[38]
    DIRECTION OUTPUT ;
    USE SIGNAL ;
    PORT
      LAYER M4 ;
        RECT  0 27.024 0.084 27.048 ;
    END
  END o[38]
  PIN o[39]
    DIRECTION OUTPUT ;
    USE SIGNAL ;
    PORT
      LAYER M4 ;
        RECT  0 27.12 0.084 27.144 ;
    END
  END o[39]
  PIN o[3]
    DIRECTION OUTPUT ;
    USE SIGNAL ;
    PORT
      LAYER M4 ;
        RECT  0 20.592 0.084 20.616 ;
    END
  END o[3]
  PIN o[40]
    DIRECTION OUTPUT ;
    USE SIGNAL ;
    PORT
      LAYER M4 ;
        RECT  0 27.216 0.084 27.24 ;
    END
  END o[40]
  PIN o[41]
    DIRECTION OUTPUT ;
    USE SIGNAL ;
    PORT
      LAYER M4 ;
        RECT  0 27.312 0.084 27.336 ;
    END
  END o[41]
  PIN o[42]
    DIRECTION OUTPUT ;
    USE SIGNAL ;
    PORT
      LAYER M4 ;
        RECT  0 27.408 0.084 27.432 ;
    END
  END o[42]
  PIN o[43]
    DIRECTION OUTPUT ;
    USE SIGNAL ;
    PORT
      LAYER M4 ;
        RECT  0 27.504 0.084 27.528 ;
    END
  END o[43]
  PIN o[44]
    DIRECTION OUTPUT ;
    USE SIGNAL ;
    PORT
      LAYER M4 ;
        RECT  0 27.6 0.084 27.624 ;
    END
  END o[44]
  PIN o[45]
    DIRECTION OUTPUT ;
    USE SIGNAL ;
    PORT
      LAYER M4 ;
        RECT  0 27.696 0.084 27.72 ;
    END
  END o[45]
  PIN o[46]
    DIRECTION OUTPUT ;
    USE SIGNAL ;
    PORT
      LAYER M4 ;
        RECT  0 27.792 0.084 27.816 ;
    END
  END o[46]
  PIN o[47]
    DIRECTION OUTPUT ;
    USE SIGNAL ;
    PORT
      LAYER M4 ;
        RECT  0 27.888 0.084 27.912 ;
    END
  END o[47]
  PIN o[48]
    DIRECTION OUTPUT ;
    USE SIGNAL ;
    PORT
      LAYER M4 ;
        RECT  0 27.984 0.084 28.008 ;
    END
  END o[48]
  PIN o[49]
    DIRECTION OUTPUT ;
    USE SIGNAL ;
    PORT
      LAYER M4 ;
        RECT  0 28.08 0.084 28.104 ;
    END
  END o[49]
  PIN o[4]
    DIRECTION OUTPUT ;
    USE SIGNAL ;
    PORT
      LAYER M4 ;
        RECT  0 20.688 0.084 20.712 ;
    END
  END o[4]
  PIN o[50]
    DIRECTION OUTPUT ;
    USE SIGNAL ;
    PORT
      LAYER M4 ;
        RECT  0 28.176 0.084 28.2 ;
    END
  END o[50]
  PIN o[51]
    DIRECTION OUTPUT ;
    USE SIGNAL ;
    PORT
      LAYER M4 ;
        RECT  0 28.272 0.084 28.296 ;
    END
  END o[51]
  PIN o[52]
    DIRECTION OUTPUT ;
    USE SIGNAL ;
    PORT
      LAYER M4 ;
        RECT  0 28.368 0.084 28.392 ;
    END
  END o[52]
  PIN o[53]
    DIRECTION OUTPUT ;
    USE SIGNAL ;
    PORT
      LAYER M4 ;
        RECT  0 28.464 0.084 28.488 ;
    END
  END o[53]
  PIN o[54]
    DIRECTION OUTPUT ;
    USE SIGNAL ;
    PORT
      LAYER M4 ;
        RECT  0 28.56 0.084 28.584 ;
    END
  END o[54]
  PIN o[55]
    DIRECTION OUTPUT ;
    USE SIGNAL ;
    PORT
      LAYER M4 ;
        RECT  0 28.656 0.084 28.68 ;
    END
  END o[55]
  PIN o[56]
    DIRECTION OUTPUT ;
    USE SIGNAL ;
    PORT
      LAYER M4 ;
        RECT  0 28.752 0.084 28.776 ;
    END
  END o[56]
  PIN o[57]
    DIRECTION OUTPUT ;
    USE SIGNAL ;
    PORT
      LAYER M4 ;
        RECT  0 28.848 0.084 28.872 ;
    END
  END o[57]
  PIN o[58]
    DIRECTION OUTPUT ;
    USE SIGNAL ;
    PORT
      LAYER M4 ;
        RECT  0 28.944 0.084 28.968 ;
    END
  END o[58]
  PIN o[59]
    DIRECTION OUTPUT ;
    USE SIGNAL ;
    PORT
      LAYER M4 ;
        RECT  0 29.04 0.084 29.064 ;
    END
  END o[59]
  PIN o[5]
    DIRECTION OUTPUT ;
    USE SIGNAL ;
    PORT
      LAYER M4 ;
        RECT  0 20.784 0.084 20.808 ;
    END
  END o[5]
  PIN o[60]
    DIRECTION OUTPUT ;
    USE SIGNAL ;
    PORT
      LAYER M4 ;
        RECT  0 29.136 0.084 29.16 ;
    END
  END o[60]
  PIN o[61]
    DIRECTION OUTPUT ;
    USE SIGNAL ;
    PORT
      LAYER M4 ;
        RECT  0 29.232 0.084 29.256 ;
    END
  END o[61]
  PIN o[62]
    DIRECTION OUTPUT ;
    USE SIGNAL ;
    PORT
      LAYER M4 ;
        RECT  0 29.328 0.084 29.352 ;
    END
  END o[62]
  PIN o[63]
    DIRECTION OUTPUT ;
    USE SIGNAL ;
    PORT
      LAYER M4 ;
        RECT  0 29.424 0.084 29.448 ;
    END
  END o[63]
  PIN o[64]
    DIRECTION OUTPUT ;
    USE SIGNAL ;
    PORT
      LAYER M4 ;
        RECT  0 11.088 0.084 11.112 ;
    END
  END o[64]
  PIN o[65]
    DIRECTION OUTPUT ;
    USE SIGNAL ;
    PORT
      LAYER M4 ;
        RECT  0 11.184 0.084 11.208 ;
    END
  END o[65]
  PIN o[66]
    DIRECTION OUTPUT ;
    USE SIGNAL ;
    PORT
      LAYER M4 ;
        RECT  0 11.28 0.084 11.304 ;
    END
  END o[66]
  PIN o[67]
    DIRECTION OUTPUT ;
    USE SIGNAL ;
    PORT
      LAYER M4 ;
        RECT  0 11.376 0.084 11.4 ;
    END
  END o[67]
  PIN o[68]
    DIRECTION OUTPUT ;
    USE SIGNAL ;
    PORT
      LAYER M4 ;
        RECT  0 11.472 0.084 11.496 ;
    END
  END o[68]
  PIN o[69]
    DIRECTION OUTPUT ;
    USE SIGNAL ;
    PORT
      LAYER M4 ;
        RECT  0 11.568 0.084 11.592 ;
    END
  END o[69]
  PIN o[6]
    DIRECTION OUTPUT ;
    USE SIGNAL ;
    PORT
      LAYER M4 ;
        RECT  0 20.88 0.084 20.904 ;
    END
  END o[6]
  PIN o[70]
    DIRECTION OUTPUT ;
    USE SIGNAL ;
    PORT
      LAYER M4 ;
        RECT  0 11.664 0.084 11.688 ;
    END
  END o[70]
  PIN o[71]
    DIRECTION OUTPUT ;
    USE SIGNAL ;
    PORT
      LAYER M4 ;
        RECT  0 11.76 0.084 11.784 ;
    END
  END o[71]
  PIN o[72]
    DIRECTION OUTPUT ;
    USE SIGNAL ;
    PORT
      LAYER M4 ;
        RECT  0 11.856 0.084 11.88 ;
    END
  END o[72]
  PIN o[73]
    DIRECTION OUTPUT ;
    USE SIGNAL ;
    PORT
      LAYER M4 ;
        RECT  0 11.952 0.084 11.976 ;
    END
  END o[73]
  PIN o[74]
    DIRECTION OUTPUT ;
    USE SIGNAL ;
    PORT
      LAYER M4 ;
        RECT  0 12.048 0.084 12.072 ;
    END
  END o[74]
  PIN o[75]
    DIRECTION OUTPUT ;
    USE SIGNAL ;
    PORT
      LAYER M4 ;
        RECT  0 12.144 0.084 12.168 ;
    END
  END o[75]
  PIN o[76]
    DIRECTION OUTPUT ;
    USE SIGNAL ;
    PORT
      LAYER M4 ;
        RECT  0 12.24 0.084 12.264 ;
    END
  END o[76]
  PIN o[77]
    DIRECTION OUTPUT ;
    USE SIGNAL ;
    PORT
      LAYER M4 ;
        RECT  0 12.336 0.084 12.36 ;
    END
  END o[77]
  PIN o[78]
    DIRECTION OUTPUT ;
    USE SIGNAL ;
    PORT
      LAYER M4 ;
        RECT  0 12.432 0.084 12.456 ;
    END
  END o[78]
  PIN o[79]
    DIRECTION OUTPUT ;
    USE SIGNAL ;
    PORT
      LAYER M4 ;
        RECT  0 12.528 0.084 12.552 ;
    END
  END o[79]
  PIN o[7]
    DIRECTION OUTPUT ;
    USE SIGNAL ;
    PORT
      LAYER M4 ;
        RECT  0 20.976 0.084 21 ;
    END
  END o[7]
  PIN o[80]
    DIRECTION OUTPUT ;
    USE SIGNAL ;
    PORT
      LAYER M4 ;
        RECT  0 12.624 0.084 12.648 ;
    END
  END o[80]
  PIN o[81]
    DIRECTION OUTPUT ;
    USE SIGNAL ;
    PORT
      LAYER M4 ;
        RECT  0 12.72 0.084 12.744 ;
    END
  END o[81]
  PIN o[82]
    DIRECTION OUTPUT ;
    USE SIGNAL ;
    PORT
      LAYER M4 ;
        RECT  0 12.816 0.084 12.84 ;
    END
  END o[82]
  PIN o[83]
    DIRECTION OUTPUT ;
    USE SIGNAL ;
    PORT
      LAYER M4 ;
        RECT  0 12.912 0.084 12.936 ;
    END
  END o[83]
  PIN o[84]
    DIRECTION OUTPUT ;
    USE SIGNAL ;
    PORT
      LAYER M4 ;
        RECT  0 13.008 0.084 13.032 ;
    END
  END o[84]
  PIN o[85]
    DIRECTION OUTPUT ;
    USE SIGNAL ;
    PORT
      LAYER M4 ;
        RECT  0 13.104 0.084 13.128 ;
    END
  END o[85]
  PIN o[86]
    DIRECTION OUTPUT ;
    USE SIGNAL ;
    PORT
      LAYER M4 ;
        RECT  0 13.2 0.084 13.224 ;
    END
  END o[86]
  PIN o[87]
    DIRECTION OUTPUT ;
    USE SIGNAL ;
    PORT
      LAYER M4 ;
        RECT  0 13.296 0.084 13.32 ;
    END
  END o[87]
  PIN o[88]
    DIRECTION OUTPUT ;
    USE SIGNAL ;
    PORT
      LAYER M4 ;
        RECT  0 13.392 0.084 13.416 ;
    END
  END o[88]
  PIN o[89]
    DIRECTION OUTPUT ;
    USE SIGNAL ;
    PORT
      LAYER M4 ;
        RECT  0 13.488 0.084 13.512 ;
    END
  END o[89]
  PIN o[8]
    DIRECTION OUTPUT ;
    USE SIGNAL ;
    PORT
      LAYER M4 ;
        RECT  0 21.072 0.084 21.096 ;
    END
  END o[8]
  PIN o[90]
    DIRECTION OUTPUT ;
    USE SIGNAL ;
    PORT
      LAYER M4 ;
        RECT  0 13.584 0.084 13.608 ;
    END
  END o[90]
  PIN o[91]
    DIRECTION OUTPUT ;
    USE SIGNAL ;
    PORT
      LAYER M4 ;
        RECT  0 13.68 0.084 13.704 ;
    END
  END o[91]
  PIN o[92]
    DIRECTION OUTPUT ;
    USE SIGNAL ;
    PORT
      LAYER M4 ;
        RECT  0 13.776 0.084 13.8 ;
    END
  END o[92]
  PIN o[93]
    DIRECTION OUTPUT ;
    USE SIGNAL ;
    PORT
      LAYER M4 ;
        RECT  0 13.872 0.084 13.896 ;
    END
  END o[93]
  PIN o[94]
    DIRECTION OUTPUT ;
    USE SIGNAL ;
    PORT
      LAYER M4 ;
        RECT  0 13.968 0.084 13.992 ;
    END
  END o[94]
  PIN o[95]
    DIRECTION OUTPUT ;
    USE SIGNAL ;
    PORT
      LAYER M4 ;
        RECT  0 14.064 0.084 14.088 ;
    END
  END o[95]
  PIN o[96]
    DIRECTION OUTPUT ;
    USE SIGNAL ;
    PORT
      LAYER M4 ;
        RECT  0 1.104 0.084 1.128 ;
    END
  END o[96]
  PIN o[97]
    DIRECTION OUTPUT ;
    USE SIGNAL ;
    PORT
      LAYER M4 ;
        RECT  0 1.2 0.084 1.224 ;
    END
  END o[97]
  PIN o[98]
    DIRECTION OUTPUT ;
    USE SIGNAL ;
    PORT
      LAYER M4 ;
        RECT  0 1.296 0.084 1.32 ;
    END
  END o[98]
  PIN o[99]
    DIRECTION OUTPUT ;
    USE SIGNAL ;
    PORT
      LAYER M4 ;
        RECT  0 1.392 0.084 1.416 ;
    END
  END o[99]
  PIN o[9]
    DIRECTION OUTPUT ;
    USE SIGNAL ;
    PORT
      LAYER M4 ;
        RECT  0 21.168 0.084 21.192 ;
    END
  END o[9]
  PIN rs
    DIRECTION INPUT ;
    USE SIGNAL ;
    PORT
      LAYER M5 ;
        RECT  17.04 30.156 17.064 30.24 ;
    END
  END rs
  PIN VDD
    DIRECTION INOUT ;
    USE POWER ;
    PORT
      LAYER M5 ;
        RECT  18.792 2.151 18.912 28.089 ;
        RECT  13.392 2.151 13.512 28.089 ;
        RECT  7.992 2.151 8.112 28.089 ;
        RECT  2.592 2.151 2.712 28.089 ;
    END
  END VDD
  PIN VSS
    DIRECTION INOUT ;
    USE GROUND ;
    PORT
      LAYER M5 ;
        RECT  18.6 2.137 18.72 28.103 ;
        RECT  13.2 2.137 13.32 28.103 ;
        RECT  7.8 2.137 7.92 28.103 ;
        RECT  2.4 2.137 2.52 28.103 ;
    END
  END VSS
  # OT_OBS_CLOSED layer=M5 d_um=1.536 added=83
  OBS
    LAYER RVTN ;
     RECT  2.16 2.16 21.6 2.295 ;
     RECT  2.16 2.565 21.6 2.835 ;
     RECT  2.16 3.105 21.6 3.375 ;
     RECT  2.16 3.645 21.6 3.915 ;
     RECT  2.16 4.185 21.6 4.455 ;
     RECT  2.16 4.725 21.6 4.995 ;
     RECT  2.16 5.265 21.6 5.535 ;
     RECT  2.16 5.805 21.6 6.075 ;
     RECT  2.16 6.345 21.6 6.615 ;
     RECT  2.16 6.885 21.6 7.155 ;
     RECT  2.16 7.425 21.6 7.695 ;
     RECT  2.16 7.965 21.6 8.235 ;
     RECT  2.16 8.505 21.6 8.775 ;
     RECT  2.16 9.045 21.6 9.315 ;
     RECT  2.16 9.585 21.6 9.855 ;
     RECT  2.16 10.125 21.6 10.395 ;
     RECT  2.16 10.665 21.6 10.935 ;
     RECT  2.16 11.205 21.6 11.475 ;
     RECT  2.16 11.745 21.6 12.015 ;
     RECT  2.16 12.285 21.6 12.555 ;
     RECT  2.16 12.825 21.6 13.095 ;
     RECT  2.16 13.365 21.6 13.635 ;
     RECT  2.16 13.905 21.6 14.175 ;
     RECT  2.16 14.445 21.6 14.715 ;
     RECT  2.16 14.985 21.6 15.255 ;
     RECT  2.16 15.525 21.6 15.795 ;
     RECT  2.16 16.065 21.6 16.335 ;
     RECT  2.16 16.605 21.6 16.875 ;
     RECT  2.16 17.145 21.6 17.415 ;
     RECT  2.16 17.685 21.6 17.955 ;
     RECT  2.16 18.225 21.6 18.495 ;
     RECT  2.16 18.765 21.6 19.035 ;
     RECT  2.16 19.305 21.6 19.575 ;
     RECT  2.16 19.845 21.6 20.115 ;
     RECT  2.16 20.385 21.6 20.655 ;
     RECT  2.16 20.925 21.6 21.195 ;
     RECT  2.16 21.465 21.6 21.735 ;
     RECT  2.16 22.005 21.6 22.275 ;
     RECT  2.16 22.545 21.6 22.815 ;
     RECT  2.16 23.085 21.6 23.355 ;
     RECT  2.16 23.625 21.6 23.895 ;
     RECT  2.16 24.165 21.6 24.435 ;
     RECT  2.16 24.705 21.6 24.975 ;
     RECT  2.16 25.245 21.6 25.515 ;
     RECT  2.16 25.785 21.6 26.055 ;
     RECT  2.16 26.325 21.6 26.595 ;
     RECT  2.16 26.865 21.6 27.135 ;
     RECT  2.16 27.405 21.6 27.675 ;
     RECT  2.16 27.945 21.6 28.08 ;
    LAYER RVTP ;
     RECT  2.16 2.295 21.6 2.565 ;
     RECT  2.16 2.835 21.6 3.105 ;
     RECT  2.16 3.375 21.6 3.645 ;
     RECT  2.16 3.915 21.6 4.185 ;
     RECT  2.16 4.455 21.6 4.725 ;
     RECT  2.16 4.995 21.6 5.265 ;
     RECT  2.16 5.535 21.6 5.805 ;
     RECT  2.16 6.075 21.6 6.345 ;
     RECT  2.16 6.615 21.6 6.885 ;
     RECT  2.16 7.155 21.6 7.425 ;
     RECT  2.16 7.695 21.6 7.965 ;
     RECT  2.16 8.235 21.6 8.505 ;
     RECT  2.16 8.775 21.6 9.045 ;
     RECT  2.16 9.315 21.6 9.585 ;
     RECT  2.16 9.855 21.6 10.125 ;
     RECT  2.16 10.395 21.6 10.665 ;
     RECT  2.16 10.935 21.6 11.205 ;
     RECT  2.16 11.475 21.6 11.745 ;
     RECT  2.16 12.015 21.6 12.285 ;
     RECT  2.16 12.555 21.6 12.825 ;
     RECT  2.16 13.095 21.6 13.365 ;
     RECT  2.16 13.635 21.6 13.905 ;
     RECT  2.16 14.175 21.6 14.445 ;
     RECT  2.16 14.715 21.6 14.985 ;
     RECT  2.16 15.255 21.6 15.525 ;
     RECT  2.16 15.795 21.6 16.065 ;
     RECT  2.16 16.335 21.6 16.605 ;
     RECT  2.16 16.875 21.6 17.145 ;
     RECT  2.16 17.415 21.6 17.685 ;
     RECT  2.16 17.955 21.6 18.225 ;
     RECT  2.16 18.495 21.6 18.765 ;
     RECT  2.16 19.035 21.6 19.305 ;
     RECT  2.16 19.575 21.6 19.845 ;
     RECT  2.16 20.115 21.6 20.385 ;
     RECT  2.16 20.655 21.6 20.925 ;
     RECT  2.16 21.195 21.6 21.465 ;
     RECT  2.16 21.735 21.6 22.005 ;
     RECT  2.16 22.275 21.6 22.545 ;
     RECT  2.16 22.815 21.6 23.085 ;
     RECT  2.16 23.355 21.6 23.625 ;
     RECT  2.16 23.895 21.6 24.165 ;
     RECT  2.16 24.435 21.6 24.705 ;
     RECT  2.16 24.975 21.6 25.245 ;
     RECT  2.16 25.515 21.6 25.785 ;
     RECT  2.16 26.055 21.6 26.325 ;
     RECT  2.16 26.595 21.6 26.865 ;
     RECT  2.16 27.135 21.6 27.405 ;
     RECT  2.16 27.675 21.6 27.945 ;
    LAYER M1 ;
     RECT  2.16 2.151 21.6 28.089 ;
    LAYER M2 ;
     RECT  0.031 26.676 0.103 27.396 ;
     RECT  0.103 26.064 0.131 27.396 ;
     RECT  0.103 5.076 0.139 5.094 ;
     RECT  0.103 6.246 0.139 7.416 ;
     RECT  0.103 13.302 0.139 13.32 ;
     RECT  0.103 14.076 0.139 14.202 ;
     RECT  0.103 20.736 0.139 20.754 ;
     RECT  0.103 24.336 0.139 25.074 ;
     RECT  0.131 26.064 0.139 27.162 ;
     RECT  0.139 13.302 0.175 14.544 ;
     RECT  0.103 15.336 0.175 16.524 ;
     RECT  0.103 3.924 0.203 3.942 ;
     RECT  0.103 17.271 0.203 18.486 ;
     RECT  0.103 19.62 0.211 19.638 ;
     RECT  0.139 20.736 0.211 21.384 ;
     RECT  0.103 22.518 0.211 23.184 ;
     RECT  0.175 13.302 0.239 16.524 ;
     RECT  0.203 17.496 0.239 18.054 ;
     RECT  0.103 10.134 0.283 10.152 ;
     RECT  0.139 5.004 0.319 5.094 ;
     RECT  0.139 6.246 0.319 7.722 ;
     RECT  0.211 19.044 0.319 21.654 ;
     RECT  0.211 22.446 0.319 23.229 ;
     RECT  0.319 19.044 0.347 23.229 ;
     RECT  0.319 5.004 0.419 7.722 ;
     RECT  0.283 10.134 0.419 10.224 ;
     RECT  0.239 13.302 0.499 14.202 ;
     RECT  0.419 10.134 0.527 10.152 ;
     RECT  0.103 11.106 0.535 11.124 ;
     RECT  0.499 11.952 0.535 11.97 ;
     RECT  0.419 5.004 0.823 5.094 ;
     RECT  0.499 13.176 1.247 14.202 ;
     RECT  1.615 3.114 1.651 3.132 ;
     RECT  1.651 3.114 1.687 3.672 ;
     RECT  0.823 4.806 1.687 5.094 ;
     RECT  1.687 3.114 2.16 5.094 ;
     RECT  0.419 6.246 2.16 7.722 ;
     RECT  0.535 11.106 2.16 11.97 ;
     RECT  1.247 13.374 2.16 14.202 ;
     RECT  0.239 15.066 2.16 16.524 ;
     RECT  0.239 18.036 2.16 18.054 ;
     RECT  0.347 19.044 2.16 23.184 ;
     RECT  0.139 24.336 2.16 27.162 ;
     RECT  2.16 2.151 2.299 28.089 ;
     RECT  2.299 2.106 2.731 28.089 ;
     RECT  2.731 2.034 3.415 28.089 ;
     RECT  3.415 1.998 3.955 28.089 ;
     RECT  3.955 1.881 5.503 28.089 ;
     RECT  5.503 1.53 6.475 28.089 ;
     RECT  7.627 29.736 8.131 29.754 ;
     RECT  8.131 29.646 8.167 29.754 ;
     RECT  8.167 29.151 8.203 29.754 ;
     RECT  6.475 1.53 8.383 28.314 ;
     RECT  8.203 29.151 8.383 29.862 ;
     RECT  7.231 0.531 8.635 0.549 ;
     RECT  8.383 1.53 9.427 29.862 ;
     RECT  8.635 0.342 9.463 0.549 ;
     RECT  9.427 1.341 9.463 29.862 ;
     RECT  9.463 0.342 10.759 29.862 ;
     RECT  10.759 0.342 16.511 29.898 ;
     RECT  16.511 0.342 17.951 28.206 ;
     RECT  17.951 0.801 18.167 28.206 ;
     RECT  16.511 29.07 18.167 29.898 ;
     RECT  18.167 2.106 18.239 28.206 ;
     RECT  18.167 29.772 18.311 29.898 ;
     RECT  18.311 29.772 18.527 29.862 ;
     RECT  18.167 0.801 19.903 1.359 ;
     RECT  18.239 2.106 19.903 28.089 ;
     RECT  19.903 0.801 20.111 28.089 ;
     RECT  20.111 1.998 20.147 28.089 ;
     RECT  18.527 29.844 20.219 29.862 ;
     RECT  20.147 2.106 20.363 28.089 ;
     RECT  20.111 0.801 20.399 0.819 ;
     RECT  20.363 2.151 21.6 28.089 ;
     RECT  21.6 16.38 21.767 16.974 ;
     RECT  21.6 23.868 22.271 26.046 ;
     RECT  21.6 10.908 22.631 15.516 ;
     RECT  21.6 2.808 22.739 2.826 ;
     RECT  21.6 7.398 22.739 8.226 ;
     RECT  22.631 12.798 22.739 15.516 ;
     RECT  21.6 22.518 22.739 23.112 ;
     RECT  22.271 23.868 22.739 24.966 ;
     RECT  22.271 26.028 22.739 26.046 ;
     RECT  21.6 27.108 22.739 27.126 ;
     RECT  21.6 3.888 22.811 3.906 ;
     RECT  21.6 4.968 22.811 4.986 ;
     RECT  22.739 7.938 22.811 8.226 ;
     RECT  22.631 10.908 22.811 11.97 ;
     RECT  22.739 13.338 22.811 14.706 ;
     RECT  21.767 16.956 22.811 16.974 ;
     RECT  22.739 23.094 22.811 23.112 ;
     RECT  22.739 24.948 22.811 24.966 ;
     RECT  21.6 5.742 23.431 6.336 ;
     RECT  23.431 5.31 23.467 6.336 ;
     RECT  22.811 7.938 23.467 7.956 ;
     RECT  23.431 12.222 23.467 12.24 ;
     RECT  23.467 3.582 23.539 3.708 ;
     RECT  22.811 10.908 23.603 11.466 ;
     RECT  23.539 3.582 23.639 3.978 ;
     RECT  23.467 5.31 23.639 6.408 ;
     RECT  23.467 7.704 23.639 7.956 ;
     RECT  23.467 12.222 23.639 12.429 ;
     RECT  23.467 24.066 23.639 24.084 ;
     RECT  23.639 3.69 23.675 3.708 ;
     RECT  23.639 5.391 23.675 6.408 ;
     RECT  23.639 7.938 23.675 7.956 ;
     RECT  23.603 11.448 23.675 11.466 ;
     RECT  23.639 12.411 23.675 12.429 ;
     RECT  22.811 13.338 23.675 13.356 ;
    LAYER M3 ;
     RECT  18.324 0.139 18.342 0.337 ;
     RECT  9.576 0.373 9.594 0.409 ;
     RECT  16.92 0.373 16.938 0.409 ;
     RECT  8.64 0.337 8.658 0.445 ;
     RECT  9.54 0.409 9.594 0.445 ;
     RECT  16.524 0.409 16.938 0.481 ;
     RECT  6.768 0.139 6.786 0.526 ;
     RECT  8.64 0.445 9.594 0.526 ;
     RECT  15.408 0.526 15.426 0.667 ;
     RECT  16.488 0.481 16.938 0.667 ;
     RECT  6.768 0.526 7.254 0.715 ;
     RECT  14.256 0.679 14.274 0.715 ;
     RECT  15.408 0.667 16.938 0.715 ;
     RECT  13.356 0.481 13.374 0.751 ;
     RECT  8.64 0.526 9.99 0.796 ;
     RECT  10.836 0.667 10.962 0.796 ;
     RECT  20.196 0.235 20.214 0.796 ;
     RECT  19.08 0.187 19.098 0.811 ;
     RECT  14.256 0.715 16.938 0.859 ;
     RECT  19.08 0.811 19.134 0.859 ;
     RECT  13.176 0.751 13.374 0.907 ;
     RECT  14.148 0.859 16.938 0.907 ;
     RECT  13.104 0.907 16.938 0.985 ;
     RECT  8.64 0.796 10.962 1.021 ;
     RECT  12.6 0.985 17.01 1.147 ;
     RECT  20.196 0.796 20.394 1.336 ;
     RECT  12.564 1.147 17.01 1.339 ;
     RECT  17.928 0.337 18.342 1.339 ;
     RECT  2.556 1.291 2.574 1.387 ;
     RECT  8.64 1.021 11.574 1.417 ;
     RECT  12.564 1.339 18.342 1.417 ;
     RECT  6.768 0.715 7.398 1.435 ;
     RECT  20.088 1.336 20.394 1.435 ;
     RECT  2.376 1.387 2.574 1.483 ;
     RECT  20.088 1.435 20.43 1.483 ;
     RECT  5.508 1.525 5.526 1.579 ;
     RECT  2.376 1.483 2.862 1.675 ;
     RECT  19.08 0.859 19.314 1.723 ;
     RECT  20.088 1.483 21.006 1.723 ;
     RECT  1.62 1.195 1.638 1.771 ;
     RECT  2.376 1.675 3.258 1.771 ;
     RECT  1.62 1.771 3.258 1.876 ;
     RECT  6.336 1.435 7.398 1.876 ;
     RECT  6.336 1.876 7.578 1.957 ;
     RECT  8.64 1.417 18.342 1.957 ;
     RECT  1.62 1.876 3.978 1.993 ;
     RECT  0.828 1.099 0.846 2.011 ;
     RECT  1.62 1.993 4.59 2.011 ;
     RECT  5.436 1.579 5.526 2.011 ;
     RECT  0.828 2.011 5.526 2.029 ;
     RECT  6.336 1.957 18.342 2.029 ;
     RECT  0.828 2.029 18.342 2.143 ;
     RECT  19.08 1.723 21.258 2.143 ;
     RECT  0.828 2.143 21.258 2.263 ;
     RECT  0.828 2.263 21.474 2.285 ;
     RECT  22.716 2.635 22.734 2.831 ;
     RECT  1.62 2.285 21.474 3.137 ;
     RECT  0.828 2.285 0.846 3.211 ;
     RECT  23.58 2.443 23.598 3.403 ;
     RECT  23.472 3.403 23.598 3.499 ;
     RECT  23.472 3.499 23.634 3.595 ;
     RECT  23.472 3.595 23.67 3.713 ;
     RECT  23.472 3.713 23.634 3.725 ;
     RECT  22.788 3.787 22.806 3.911 ;
     RECT  0.144 3.211 0.846 3.916 ;
     RECT  1.656 3.137 21.474 3.965 ;
     RECT  0.108 3.916 0.846 3.979 ;
     RECT  1.656 3.965 21.438 3.979 ;
     RECT  23.544 3.725 23.634 3.983 ;
     RECT  0.108 3.979 21.438 4.109 ;
     RECT  23.58 3.983 23.598 4.157 ;
     RECT  0.144 4.109 21.438 4.289 ;
     RECT  0.144 4.289 1.17 4.445 ;
     RECT  2.232 4.289 21.402 4.685 ;
     RECT  0.144 4.445 0.846 4.829 ;
     RECT  0.144 4.829 0.342 5.071 ;
     RECT  22.788 4.939 22.806 5.131 ;
     RECT  0.108 5.071 0.342 5.165 ;
     RECT  22.788 5.131 23.49 5.227 ;
     RECT  0.144 5.165 0.342 5.261 ;
     RECT  22.788 5.227 23.634 5.323 ;
     RECT  0.324 5.261 0.342 5.563 ;
     RECT  0.324 5.563 0.414 5.639 ;
     RECT  2.304 4.685 21.402 5.755 ;
     RECT  22.788 5.323 23.67 5.765 ;
     RECT  2.304 5.755 21.69 5.789 ;
     RECT  12.06 5.789 21.69 5.981 ;
     RECT  12.06 5.981 21.402 6.035 ;
     RECT  0.324 5.639 0.342 6.241 ;
     RECT  23.472 5.765 23.67 6.413 ;
     RECT  0.108 6.241 0.342 6.421 ;
     RECT  23.472 6.413 23.49 6.509 ;
     RECT  2.304 5.789 11.322 6.575 ;
     RECT  2.34 6.575 11.322 6.655 ;
     RECT  12.06 6.035 21.222 6.655 ;
     RECT  2.34 6.655 21.222 6.781 ;
     RECT  0.108 6.421 0.558 6.989 ;
     RECT  0.108 6.989 0.342 7.181 ;
     RECT  2.34 6.781 21.366 7.231 ;
     RECT  22.716 6.955 22.734 7.421 ;
     RECT  22.788 7.435 23.454 7.483 ;
     RECT  22.788 7.483 23.562 7.627 ;
     RECT  22.788 7.627 23.634 7.723 ;
     RECT  0.108 7.181 0.198 7.757 ;
     RECT  22.788 7.723 23.67 7.757 ;
     RECT  2.34 7.231 21.402 7.771 ;
     RECT  23.544 7.757 23.67 7.853 ;
     RECT  23.58 7.853 23.67 7.961 ;
     RECT  2.304 7.771 21.402 8.041 ;
     RECT  0.108 7.757 0.162 8.045 ;
     RECT  22.788 7.757 22.806 8.231 ;
     RECT  23.58 7.961 23.598 8.525 ;
     RECT  0.144 8.045 0.162 8.621 ;
     RECT  1.26 8.395 1.278 8.683 ;
     RECT  2.268 8.041 21.438 8.683 ;
     RECT  1.26 8.683 21.438 8.807 ;
     RECT  9.36 8.807 21.402 8.969 ;
     RECT  1.26 8.807 8.586 9.259 ;
     RECT  1.152 9.259 8.586 9.553 ;
     RECT  1.152 9.553 8.622 9.883 ;
     RECT  9.396 8.969 21.402 9.883 ;
     RECT  1.152 9.883 21.402 10.109 ;
     RECT  0.324 10.027 0.342 10.12 ;
     RECT  0.108 10.12 0.342 10.129 ;
     RECT  0.108 10.129 0.522 10.157 ;
     RECT  0.288 10.157 0.522 10.253 ;
     RECT  23.58 10.795 23.598 10.931 ;
     RECT  22.788 11.173 22.806 11.213 ;
     RECT  1.692 10.109 21.402 11.309 ;
     RECT  23.652 11.083 23.67 11.471 ;
     RECT  0.108 11.101 0.126 11.563 ;
     RECT  0.108 11.563 0.342 11.693 ;
     RECT  0.144 11.693 0.342 11.749 ;
     RECT  1.152 11.551 1.17 11.749 ;
     RECT  0.144 11.749 1.17 11.777 ;
     RECT  22.716 11.467 22.734 11.947 ;
     RECT  22.716 11.947 22.806 12.043 ;
     RECT  2.232 11.309 21.402 12.047 ;
     RECT  22.716 12.043 23.634 12.139 ;
     RECT  22.68 12.139 23.634 12.187 ;
     RECT  22.608 12.187 23.634 12.235 ;
     RECT  0.144 11.777 0.558 12.317 ;
     RECT  2.304 12.047 21.402 12.413 ;
     RECT  22.608 12.235 23.67 12.413 ;
     RECT  22.608 12.413 22.734 12.551 ;
     RECT  0.504 12.317 0.558 12.619 ;
     RECT  22.716 12.551 22.734 12.821 ;
     RECT  0.504 12.619 1.17 12.859 ;
     RECT  12.744 12.413 21.402 13.019 ;
     RECT  23.472 12.413 23.67 13.037 ;
     RECT  0.504 12.859 1.242 13.147 ;
     RECT  2.304 12.413 12.006 13.171 ;
     RECT  12.744 13.019 21.33 13.171 ;
     RECT  0.18 13.147 1.242 13.195 ;
     RECT  23.652 13.037 23.67 13.361 ;
     RECT  0.108 13.195 1.242 13.433 ;
     RECT  0.108 13.433 1.17 13.469 ;
     RECT  2.304 13.171 21.33 13.517 ;
     RECT  12.672 13.517 21.33 13.559 ;
     RECT  12.672 13.559 21.114 13.661 ;
     RECT  23.58 13.963 23.598 14.237 ;
     RECT  0.108 13.469 0.558 14.381 ;
     RECT  2.304 13.517 11.826 14.413 ;
     RECT  12.816 13.661 21.114 14.413 ;
     RECT  22.788 13.864 22.806 14.485 ;
     RECT  2.304 14.413 21.402 14.525 ;
     RECT  22.752 14.485 22.806 14.635 ;
     RECT  12.744 14.525 21.402 14.639 ;
     RECT  22.716 14.635 22.806 14.711 ;
     RECT  12.744 14.639 21.33 14.783 ;
     RECT  22.716 14.711 22.734 14.923 ;
     RECT  22.572 14.923 22.734 15.251 ;
     RECT  0.144 14.381 0.558 15.331 ;
     RECT  22.716 15.251 22.734 15.521 ;
     RECT  12.744 14.783 21.114 15.529 ;
     RECT  0.108 15.331 0.558 15.533 ;
     RECT  2.304 14.525 11.862 15.565 ;
     RECT  12.708 15.529 21.114 15.565 ;
     RECT  2.304 15.565 11.934 15.787 ;
     RECT  2.304 15.787 11.97 15.899 ;
     RECT  2.412 15.899 11.97 16.033 ;
     RECT  12.708 15.565 21.402 16.033 ;
     RECT  0.108 15.533 0.342 16.205 ;
     RECT  2.412 16.033 21.402 16.375 ;
     RECT  1.152 16.315 1.17 16.493 ;
     RECT  23.58 15.499 23.598 16.541 ;
     RECT  2.412 16.375 21.762 16.589 ;
     RECT  2.412 16.589 21.474 16.645 ;
     RECT  2.34 16.645 21.474 16.747 ;
     RECT  22.788 16.411 22.806 16.979 ;
     RECT  0.108 16.205 0.126 17.083 ;
     RECT  0.108 17.083 0.162 17.179 ;
     RECT  0.108 17.179 0.198 17.323 ;
     RECT  0.108 17.323 0.342 17.453 ;
     RECT  2.304 16.747 21.474 18.059 ;
     RECT  22.788 18.043 22.806 18.221 ;
     RECT  0.108 17.453 0.27 18.235 ;
     RECT  0.108 18.235 0.342 18.461 ;
     RECT  0.108 18.461 0.234 18.605 ;
     RECT  23.652 19.051 23.67 19.181 ;
     RECT  0.144 18.605 0.234 19.273 ;
     RECT  2.304 18.059 21.402 19.291 ;
     RECT  2.304 19.291 21.474 19.337 ;
     RECT  0.144 19.273 0.558 19.612 ;
     RECT  0.108 19.612 0.558 19.757 ;
     RECT  0.18 19.757 0.558 19.805 ;
     RECT  0.216 19.805 0.558 19.853 ;
     RECT  2.304 19.337 21.402 20.381 ;
     RECT  2.304 20.381 21.366 20.461 ;
     RECT  2.268 20.461 21.366 20.525 ;
     RECT  0.216 19.853 0.342 20.731 ;
     RECT  2.304 20.525 21.366 20.849 ;
     RECT  2.376 20.849 21.366 21.271 ;
     RECT  0.108 20.731 0.342 21.485 ;
     RECT  2.376 21.271 21.402 21.811 ;
     RECT  2.34 21.811 21.402 22.037 ;
     RECT  2.34 22.037 21.366 22.081 ;
     RECT  0.18 21.485 0.342 22.411 ;
     RECT  22.716 22.315 22.734 22.541 ;
     RECT  0.108 22.411 0.342 22.549 ;
     RECT  2.304 22.081 21.366 22.649 ;
     RECT  2.34 22.649 21.366 22.783 ;
     RECT  22.788 23.08 22.806 23.117 ;
     RECT  2.34 22.783 21.474 23.387 ;
     RECT  0.108 22.549 0.522 23.789 ;
     RECT  2.34 23.387 21.402 23.791 ;
     RECT  2.304 23.791 21.402 23.819 ;
     RECT  23.58 23.755 23.598 23.947 ;
     RECT  23.508 23.947 23.598 24.043 ;
     RECT  23.508 24.043 23.634 24.061 ;
     RECT  23.472 24.061 23.634 24.089 ;
     RECT  2.304 23.819 21.258 24.097 ;
     RECT  23.472 24.089 23.49 24.173 ;
     RECT  2.268 24.097 21.258 24.571 ;
     RECT  22.716 23.467 22.734 24.907 ;
     RECT  22.716 24.907 22.806 25.285 ;
     RECT  0.108 23.789 0.342 25.325 ;
     RECT  22.248 25.285 22.806 25.421 ;
     RECT  22.716 25.421 22.806 25.565 ;
     RECT  23.58 25.195 23.598 25.565 ;
     RECT  2.268 24.571 21.402 25.745 ;
     RECT  2.304 25.745 21.402 25.771 ;
     RECT  2.304 25.771 21.474 25.817 ;
     RECT  1.152 25.819 1.17 25.963 ;
     RECT  22.716 25.565 22.734 26.051 ;
     RECT  0.108 25.325 0.198 26.587 ;
     RECT  0.108 26.587 0.27 26.671 ;
     RECT  1.152 25.963 1.278 26.699 ;
     RECT  2.304 25.817 21.402 26.761 ;
     RECT  23.58 26.587 23.598 26.765 ;
     RECT  2.232 26.761 21.402 26.813 ;
     RECT  22.716 26.923 22.734 27.131 ;
     RECT  0.036 26.671 0.27 27.139 ;
     RECT  2.268 26.813 21.402 27.365 ;
     RECT  0.036 27.139 0.558 27.401 ;
     RECT  2.304 27.365 21.402 27.533 ;
     RECT  0.108 27.401 0.558 27.629 ;
     RECT  2.34 27.533 21.402 27.635 ;
     RECT  2.376 27.635 11.682 27.869 ;
     RECT  12.564 27.635 21.33 27.869 ;
     RECT  12.564 27.869 21.258 27.905 ;
     RECT  3.816 27.869 11.682 27.941 ;
     RECT  12.564 27.905 19.062 27.965 ;
     RECT  2.412 27.869 2.826 28.013 ;
     RECT  20.124 27.905 20.61 28.049 ;
     RECT  2.415 28.013 2.826 28.097 ;
     RECT  0.108 27.629 0.234 28.109 ;
     RECT  0.216 28.109 0.234 28.205 ;
     RECT  5.112 27.941 11.682 28.319 ;
     RECT  7.02 28.319 11.682 28.397 ;
     RECT  12.564 27.965 18.774 28.517 ;
     RECT  5.112 28.319 6.138 28.589 ;
     RECT  2.556 28.097 2.826 28.685 ;
     RECT  12.564 28.517 13.518 28.715 ;
     RECT  12.672 28.715 13.518 28.733 ;
     RECT  14.256 28.517 18.774 28.733 ;
     RECT  2.736 28.685 2.826 28.781 ;
     RECT  13.104 28.733 13.518 28.823 ;
     RECT  14.4 28.733 18.774 28.823 ;
     RECT  5.436 28.589 6.138 28.877 ;
     RECT  3.888 27.941 4.122 28.973 ;
     RECT  20.124 28.049 20.214 28.973 ;
     RECT  2.736 28.781 2.754 29.069 ;
     RECT  13.5 28.823 13.518 29.129 ;
     RECT  1.404 26.761 1.422 29.165 ;
     RECT  7.632 28.397 11.682 29.165 ;
     RECT  14.688 28.823 18.774 29.165 ;
     RECT  14.688 29.165 16.362 29.174 ;
     RECT  14.688 29.174 14.742 29.213 ;
     RECT  10.584 29.165 11.682 29.219 ;
     RECT  7.632 29.165 9.666 29.255 ;
     RECT  15.48 29.174 16.362 29.255 ;
     RECT  3.996 28.973 4.122 29.261 ;
     RECT  7.632 29.255 8.946 29.291 ;
     RECT  15.84 29.255 16.362 29.291 ;
     RECT  17.172 29.165 18.774 29.309 ;
     RECT  3.996 29.261 4.014 29.357 ;
     RECT  7.632 29.291 8.874 29.357 ;
     RECT  14.724 29.213 14.742 29.357 ;
     RECT  6.12 28.877 6.138 29.453 ;
     RECT  10.584 29.219 11.358 29.669 ;
     RECT  17.172 29.309 17.37 29.669 ;
     RECT  10.584 29.669 11.142 29.693 ;
     RECT  17.352 29.669 17.37 29.693 ;
     RECT  10.584 29.693 10.818 29.741 ;
     RECT  18.288 29.309 18.774 29.741 ;
     RECT  7.632 29.357 8.262 29.759 ;
     RECT  15.84 29.291 15.894 29.759 ;
     RECT  10.692 29.741 10.818 29.789 ;
     RECT  18.288 29.741 18.558 29.789 ;
     RECT  10.692 29.789 10.782 29.795 ;
     RECT  18.288 29.789 18.522 29.795 ;
     RECT  8.208 29.759 8.262 29.831 ;
     RECT  15.876 29.759 15.894 29.831 ;
     RECT  8.208 29.831 8.226 29.867 ;
     RECT  20.196 28.973 20.214 29.867 ;
     RECT  18.288 29.795 18.486 29.885 ;
     RECT  10.764 29.795 10.782 29.903 ;
     RECT  18.288 29.885 18.306 29.903 ;
    LAYER M4 ;
     RECT  0.06 1.104 0.857 29.448 ;
     RECT  0.857 1.2 1.649 29.448 ;
     RECT  1.649 1.296 2.585 29.448 ;
     RECT  2.585 1.488 2.873 29.448 ;
     RECT  2.873 1.584 4.241 29.448 ;
     RECT  4.241 1.584 4.313 6.888 ;
     RECT  4.241 7.872 4.925 29.448 ;
     RECT  4.925 7.872 5.249 9.096 ;
     RECT  4.313 1.584 5.897 6.792 ;
     RECT  5.897 1.584 6.005 2.664 ;
     RECT  4.925 10.128 6.077 29.448 ;
     RECT  5.249 8.448 6.109 9.096 ;
     RECT  6.077 10.128 6.109 28.392 ;
     RECT  6.077 29.424 6.149 29.448 ;
     RECT  5.897 3.792 6.217 6.792 ;
     RECT  6.005 1.584 6.325 2.52 ;
     RECT  6.217 3.792 6.433 6.984 ;
     RECT  6.109 8.448 6.433 28.392 ;
     RECT  6.037 0.384 6.565 0.408 ;
     RECT  6.565 0.192 6.757 0.408 ;
     RECT  6.757 0.144 6.949 0.408 ;
     RECT  6.325 1.44 6.949 2.52 ;
     RECT  6.325 29.472 7.141 29.496 ;
     RECT  6.949 0.144 7.261 2.52 ;
     RECT  6.433 3.792 7.261 28.392 ;
     RECT  7.261 0.144 7.333 28.392 ;
     RECT  7.141 29.376 7.333 29.496 ;
     RECT  7.333 0.144 8.629 29.496 ;
     RECT  8.629 0.144 9.397 29.832 ;
     RECT  9.397 0.144 16.933 29.88 ;
     RECT  16.933 0.144 17.795 30.12 ;
     RECT  17.795 0.144 18.353 29.88 ;
     RECT  18.353 0.192 18.497 29.88 ;
     RECT  18.497 0.192 18.569 29.784 ;
     RECT  18.569 0.192 18.785 29.736 ;
     RECT  18.785 0.192 19.109 29.256 ;
     RECT  19.109 0.24 19.139 29.256 ;
     RECT  19.139 0.24 19.427 29.112 ;
     RECT  19.427 0.24 20.153 28.968 ;
     RECT  20.153 0.24 20.225 28.728 ;
     RECT  20.225 0.816 20.339 28.728 ;
     RECT  20.339 0.816 21.637 28.584 ;
     RECT  21.637 0.72 23.724 28.584 ;
    LAYER M5 ;
     RECT  6.576 0.181 6.6 0.229 ;
     RECT  6.576 0.229 7.464 0.277 ;
     RECT  17.376 0.277 17.4 0.325 ;
     RECT  6.576 0.277 7.608 0.373 ;
     RECT  17.376 0.325 17.544 0.373 ;
     RECT  10.752 0.421 10.776 0.469 ;
     RECT  14.832 0.421 14.856 0.469 ;
     RECT  10.656 0.469 10.776 0.517 ;
     RECT  10.56 0.517 10.776 0.565 ;
     RECT  14.736 0.469 14.856 0.565 ;
     RECT  10.56 0.565 11.4 0.613 ;
     RECT  14.304 0.565 14.856 0.613 ;
     RECT  6.048 0.373 7.608 0.757 ;
     RECT  17.376 0.373 17.688 0.757 ;
     RECT  10.224 0.613 11.4 0.853 ;
     RECT  13.584 0.613 14.856 0.853 ;
     RECT  15.84 0.517 15.864 0.853 ;
     RECT  17.136 0.757 17.688 0.901 ;
     RECT  20.448 0.805 20.472 0.901 ;
     RECT  17.136 0.901 17.784 0.997 ;
     RECT  13.584 0.853 15.864 1.045 ;
     RECT  17.136 0.997 18.12 1.045 ;
     RECT  9.648 0.853 11.4 1.093 ;
     RECT  21.648 0.709 21.672 1.093 ;
     RECT  13.584 1.045 18.12 1.141 ;
     RECT  19.92 0.901 20.472 1.189 ;
     RECT  6.048 0.757 8.232 1.237 ;
     RECT  9.648 1.093 11.544 1.237 ;
     RECT  13.104 1.141 18.12 1.285 ;
     RECT  19.872 1.189 20.472 1.285 ;
     RECT  6.048 1.237 11.544 1.381 ;
     RECT  19.824 1.285 20.472 1.381 ;
     RECT  19.344 1.381 20.472 1.573 ;
     RECT  21.6 1.093 21.672 1.573 ;
     RECT  6.048 1.381 12.072 1.619 ;
     RECT  13.104 1.285 18.36 1.621 ;
     RECT  19.344 1.573 21.672 1.621 ;
     RECT  2.4 2.137 2.52 2.151 ;
     RECT  6.048 1.619 11.976 2.435 ;
     RECT  3.936 2.485 3.96 2.627 ;
     RECT  6.048 2.435 11.592 2.915 ;
     RECT  13.104 1.621 21.672 2.965 ;
     RECT  10.032 2.915 11.592 3.397 ;
     RECT  12.864 2.965 21.672 3.397 ;
     RECT  10.032 3.397 21.672 4.019 ;
     RECT  10.032 4.019 21.096 4.067 ;
     RECT  0.144 3.733 0.168 4.499 ;
     RECT  10.032 4.067 11.592 4.595 ;
     RECT  10.8 4.595 11.592 4.979 ;
     RECT  11.568 4.979 11.592 5.029 ;
     RECT  12.816 4.067 21.096 5.029 ;
     RECT  11.568 5.029 21.096 5.123 ;
     RECT  6.048 2.915 9.048 5.171 ;
     RECT  17.04 5.123 21.096 5.701 ;
     RECT  6.24 5.171 9.048 5.747 ;
     RECT  17.04 5.701 21.72 5.987 ;
     RECT  0.144 5.509 0.168 6.035 ;
     RECT  11.568 5.123 15.816 6.083 ;
     RECT  12.24 6.083 15.816 6.181 ;
     RECT  17.04 5.987 21.672 6.181 ;
     RECT  12.24 6.181 21.672 6.323 ;
     RECT  10.512 6.469 10.536 6.803 ;
     RECT  12.24 6.323 21.096 7.093 ;
     RECT  12 7.093 21.096 7.333 ;
     RECT  23.568 5.461 23.592 7.715 ;
     RECT  6.48 5.747 9.048 7.909 ;
     RECT  6.48 7.909 9.384 7.957 ;
     RECT  6.48 7.957 9.48 8.003 ;
     RECT  10.8 7.909 10.824 8.437 ;
     RECT  12 7.333 21.672 8.437 ;
     RECT  10.8 8.437 21.672 8.579 ;
     RECT  10.8 8.579 20.808 8.917 ;
     RECT  6.576 8.003 9.48 9.061 ;
     RECT  10.656 8.917 20.808 9.107 ;
     RECT  1.152 8.245 1.176 9.587 ;
     RECT  6.576 9.061 9.528 9.589 ;
     RECT  6.24 9.589 9.528 9.637 ;
     RECT  10.752 9.107 20.808 9.637 ;
     RECT  10.752 9.637 20.856 9.683 ;
     RECT  11.472 9.683 20.856 10.021 ;
     RECT  11.472 10.021 21.672 10.355 ;
     RECT  6.24 9.637 9.624 10.453 ;
     RECT  16.656 10.355 21.672 10.643 ;
     RECT  2.4 2.151 2.712 11.221 ;
     RECT  2.304 11.221 2.712 11.411 ;
     RECT  16.704 10.643 21.672 11.507 ;
     RECT  11.472 10.355 15.624 11.603 ;
     RECT  16.704 11.507 21.096 12.035 ;
     RECT  16.704 12.035 21.048 12.179 ;
     RECT  12.144 11.603 15.624 12.229 ;
     RECT  23.568 12.181 23.592 12.371 ;
     RECT  16.704 12.179 21 12.611 ;
     RECT  12.144 12.229 15.672 12.853 ;
     RECT  16.704 12.611 20.856 12.853 ;
     RECT  12.144 12.853 20.856 13.189 ;
     RECT  10.8 12.949 10.824 13.235 ;
     RECT  12.048 13.189 20.856 13.283 ;
     RECT  12.048 13.283 20.568 13.621 ;
     RECT  12 13.621 20.568 13.859 ;
     RECT  12.048 13.859 20.568 14.291 ;
     RECT  21.648 15.013 21.672 15.397 ;
     RECT  12.528 14.291 20.568 15.781 ;
     RECT  21.6 15.397 21.672 15.781 ;
     RECT  11.664 15.781 20.568 15.829 ;
     RECT  21.552 15.781 21.672 15.829 ;
     RECT  11.664 15.829 21.672 16.501 ;
     RECT  11.424 16.501 21.672 16.547 ;
     RECT  12.672 16.547 21.672 16.979 ;
     RECT  11.424 16.547 11.688 17.461 ;
     RECT  12.72 16.979 21.672 18.275 ;
     RECT  11.328 17.461 11.688 18.611 ;
     RECT  4.128 18.565 4.152 18.755 ;
     RECT  12.72 18.275 21.624 18.851 ;
     RECT  12.72 18.851 21.576 19.091 ;
     RECT  6.144 10.453 9.624 19.477 ;
     RECT  11.424 18.611 11.688 19.619 ;
     RECT  11.664 19.619 11.688 19.717 ;
     RECT  12.72 19.091 21.24 19.717 ;
     RECT  6.144 19.477 10.296 19.811 ;
     RECT  11.664 19.717 21.24 20.149 ;
     RECT  0.144 20.101 0.168 20.387 ;
     RECT  11.664 20.149 21.288 20.437 ;
     RECT  11.664 20.437 21.384 20.771 ;
     RECT  0.192 20.629 0.216 21.011 ;
     RECT  5.088 20.341 5.112 21.155 ;
     RECT  6.144 19.811 9.528 21.443 ;
     RECT  16.512 20.771 21.384 21.731 ;
     RECT  11.664 20.771 15.48 21.829 ;
     RECT  0.144 21.733 0.168 22.019 ;
     RECT  11.664 21.829 15.576 22.163 ;
     RECT  16.704 21.731 21.384 22.165 ;
     RECT  6.144 21.443 9.432 22.259 ;
     RECT  11.664 22.163 15.384 22.259 ;
     RECT  12.48 22.259 15.384 22.403 ;
     RECT  16.704 22.165 21.672 22.741 ;
     RECT  16.656 22.741 21.672 22.789 ;
     RECT  16.464 22.789 21.672 23.027 ;
     RECT  12.528 22.403 15.384 23.317 ;
     RECT  16.464 23.027 21.288 23.317 ;
     RECT  12.528 23.317 21.288 23.509 ;
     RECT  2.4 11.411 2.712 24.133 ;
     RECT  11.472 23.509 21.288 24.227 ;
     RECT  11.472 24.227 12.024 24.277 ;
     RECT  23.568 24.133 23.592 24.419 ;
     RECT  0.144 24.181 0.168 24.467 ;
     RECT  11.424 24.277 12.024 24.707 ;
     RECT  13.056 24.227 21.288 24.755 ;
     RECT  11.904 24.707 12.024 24.851 ;
     RECT  2.304 24.133 2.712 25.283 ;
     RECT  6.336 22.259 9.432 25.381 ;
     RECT  13.2 24.755 21.288 25.381 ;
     RECT  11.952 24.851 12.024 26.003 ;
     RECT  6.336 25.381 9.672 26.243 ;
     RECT  12 26.003 12.024 26.435 ;
     RECT  13.2 25.381 21.672 26.483 ;
     RECT  13.2 26.483 21.096 26.485 ;
     RECT  13.104 26.485 21.096 26.819 ;
     RECT  13.104 26.819 20.52 26.965 ;
     RECT  6.336 26.243 9.432 27.301 ;
     RECT  10.8 25.909 10.824 27.395 ;
     RECT  11.952 27.301 11.976 27.589 ;
     RECT  13.056 26.965 20.52 27.589 ;
     RECT  11.952 27.589 20.52 27.829 ;
     RECT  2.4 25.283 2.712 28.089 ;
     RECT  2.4 28.089 2.52 28.103 ;
     RECT  11.952 27.829 20.952 28.115 ;
     RECT  6.24 27.301 9.432 28.259 ;
     RECT  12.528 28.115 20.952 28.499 ;
     RECT  13.632 28.499 20.952 28.595 ;
     RECT  12.528 28.499 12.552 28.643 ;
     RECT  13.632 28.595 20.328 28.739 ;
     RECT  13.632 28.739 19.8 28.787 ;
     RECT  13.632 28.787 19.416 28.931 ;
     RECT  13.632 28.931 13.656 29.027 ;
     RECT  15.264 28.931 19.416 29.123 ;
     RECT  15.264 29.123 19.128 29.267 ;
     RECT  6.336 28.259 9.432 29.411 ;
     RECT  15.264 29.267 18.456 29.411 ;
     RECT  7.68 29.411 9.432 29.459 ;
     RECT  15.648 29.411 18.456 29.459 ;
     RECT  6.336 29.411 6.36 29.507 ;
     RECT  15.648 29.459 17.784 29.507 ;
     RECT  8.64 29.459 9.432 29.843 ;
     RECT  15.648 29.507 15.672 29.843 ;
     RECT  9.408 29.843 9.432 29.891 ;
     RECT  16.944 29.507 17.784 30.131 ;
     RECT  16.944 30.131 17.064 30.224 ;
     RECT  14.856 0.517 15.84 0.853 ;
     RECT  15.864 0.517 17.376 0.757 ;
     RECT  15.864 0.757 17.136 1.045 ;
     RECT  20.472 0.805 21.648 1.093 ;
     RECT  8.232 0.853 9.648 1.237 ;
     RECT  20.472 1.093 21.6 1.573 ;
     RECT  18.36 1.285 19.824 1.381 ;
     RECT  12.072 1.381 13.104 1.619 ;
     RECT  18.36 1.381 19.344 1.621 ;
     RECT  11.976 1.619 13.104 2.435 ;
     RECT  11.592 2.435 13.104 2.965 ;
     RECT  2.712 2.485 3.936 2.627 ;
     RECT  9.048 2.915 10.032 4.595 ;
     RECT  11.592 2.965 12.864 3.397 ;
     RECT  11.592 4.067 12.816 5.029 ;
     RECT  0.144 4.499 0.168 5.509 ;
     RECT  10.8 4.979 11.568 6.083 ;
     RECT  15.816 5.123 17.04 6.181 ;
     RECT  10.8 6.083 12.24 6.469 ;
     RECT  21.096 6.323 21.672 7.333 ;
     RECT  9.048 6.469 10.512 6.803 ;
     RECT  10.536 6.469 12.24 6.803 ;
     RECT  9.048 6.803 12.24 7.093 ;
     RECT  9.048 7.093 12 7.909 ;
     RECT  9.384 7.909 10.8 7.957 ;
     RECT  10.824 7.909 12 8.437 ;
     RECT  9.48 7.957 10.8 8.917 ;
     RECT  1.176 8.245 2.4 9.587 ;
     RECT  20.808 8.579 21.672 9.637 ;
     RECT  9.48 8.917 10.656 9.061 ;
     RECT  9.528 9.061 10.656 9.107 ;
     RECT  9.528 9.107 10.752 9.637 ;
     RECT  9.624 9.637 10.752 9.683 ;
     RECT  20.856 9.637 21.672 10.021 ;
     RECT  15.624 10.355 16.656 10.643 ;
     RECT  15.624 10.643 16.704 12.229 ;
     RECT  11.472 11.603 12.144 12.949 ;
     RECT  15.672 12.229 16.704 12.853 ;
     RECT  9.624 12.949 10.8 13.235 ;
     RECT  10.824 12.949 12.144 13.189 ;
     RECT  10.824 13.189 12.048 13.235 ;
     RECT  12 13.235 12.048 13.621 ;
     RECT  12.048 14.291 12.528 15.781 ;
     RECT  20.568 15.013 21.648 15.397 ;
     RECT  20.568 15.397 21.6 15.781 ;
     RECT  20.568 15.781 21.552 15.829 ;
     RECT  11.688 16.547 12.672 16.979 ;
     RECT  11.688 16.979 12.72 19.717 ;
     RECT  2.712 18.565 4.128 18.755 ;
     RECT  11.328 18.611 11.424 19.477 ;
     RECT  21.24 19.091 21.384 20.149 ;
     RECT  10.296 19.477 11.424 19.619 ;
     RECT  10.296 19.619 11.664 19.811 ;
     RECT  21.288 20.149 21.384 20.437 ;
     RECT  5.112 20.341 6.144 21.155 ;
     RECT  0.144 20.387 0.168 20.629 ;
     RECT  0.144 20.629 0.192 21.011 ;
     RECT  15.48 20.771 16.512 21.731 ;
     RECT  0.144 21.011 0.168 21.733 ;
     RECT  15.48 21.731 16.704 21.829 ;
     RECT  15.576 21.829 16.704 22.163 ;
     RECT  15.384 22.163 16.704 22.741 ;
     RECT  11.664 22.259 12.48 22.403 ;
     RECT  11.664 22.403 12.528 23.509 ;
     RECT  15.384 22.741 16.656 22.789 ;
     RECT  15.384 22.789 16.464 23.317 ;
     RECT  12.024 24.227 13.056 24.755 ;
     RECT  11.424 24.707 11.904 24.851 ;
     RECT  12.024 24.755 13.2 26.435 ;
     RECT  11.424 24.851 11.952 25.909 ;
     RECT  9.672 25.909 10.8 26.243 ;
     RECT  10.824 25.909 11.952 26.003 ;
     RECT  10.824 26.003 12 26.435 ;
     RECT  9.432 26.243 10.8 27.395 ;
     RECT  10.824 26.435 13.2 26.485 ;
     RECT  10.824 26.485 13.104 26.965 ;
     RECT  20.52 26.819 20.952 27.829 ;
     RECT  10.824 26.965 13.056 27.301 ;
     RECT  10.824 27.301 11.952 27.395 ;
     RECT  11.976 27.301 13.056 27.589 ;
     RECT  12.552 28.499 13.632 28.643 ;
     RECT  6.36 29.411 7.68 29.459 ;
     RECT  15.672 29.507 16.944 29.843 ;
  END
END dsfd_rly_283_EW
END LIBRARY
